VERSION 5.7 ;
  NOWIREEXTENSIONATPIN ON ;
  DIVIDERCHAR "/" ;
  BUSBITCHARS "[]" ;
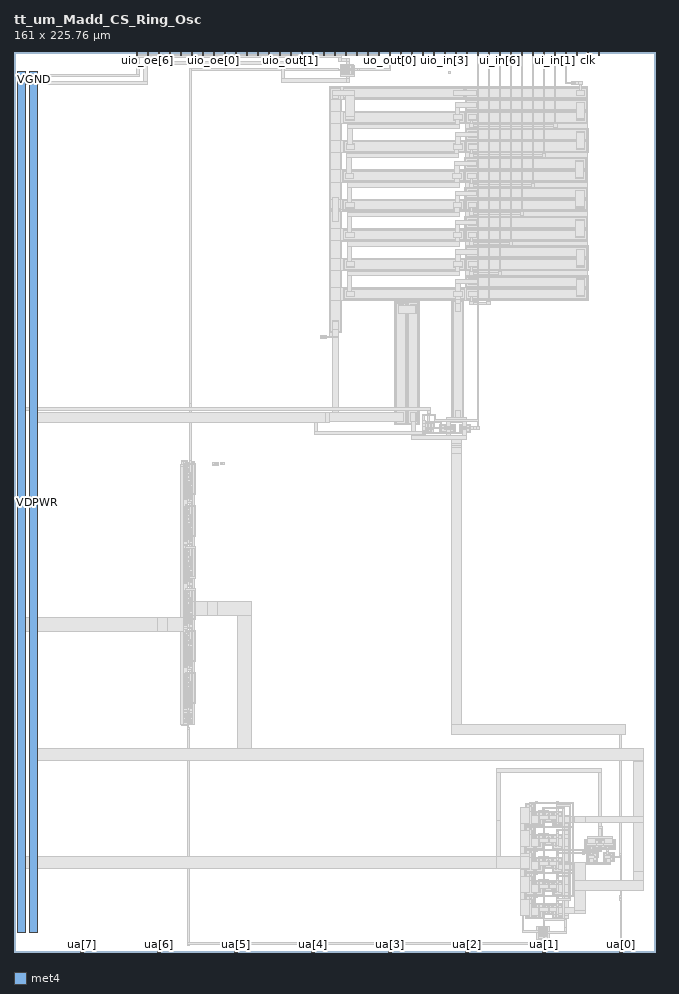
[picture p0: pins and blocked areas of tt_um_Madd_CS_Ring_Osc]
MACRO tt_um_Madd_CS_Ring_Osc
  CLASS BLOCK ;
  FOREIGN tt_um_Madd_CS_Ring_Osc ;
  ORIGIN 0.000 0.000 ;
  SIZE 161.000 BY 225.760 ;
  PIN clk
    DIRECTION INPUT ;
    USE SIGNAL ;
    PORT
      LAYER met4 ;
        RECT 143.830 224.760 144.130 225.760 ;
    END
  END clk
  PIN ena
    DIRECTION INPUT ;
    USE SIGNAL ;
    PORT
      LAYER met4 ;
        RECT 146.590 224.760 146.890 225.760 ;
    END
  END ena
  PIN rst_n
    DIRECTION INPUT ;
    USE SIGNAL ;
    PORT
      LAYER met4 ;
        RECT 141.070 224.760 141.370 225.760 ;
    END
  END rst_n
  PIN ua[0]
    DIRECTION INOUT ;
    USE SIGNAL ;
    ANTENNAGATEAREA 0.500000 ;
    ANTENNADIFFAREA 0.870000 ;
    PORT
      LAYER met4 ;
        RECT 151.810 0.000 152.710 1.000 ;
    END
  END ua[0]
  PIN ua[1]
    DIRECTION INOUT ;
    USE SIGNAL ;
    ANTENNAGATEAREA 0.247500 ;
    ANTENNADIFFAREA 0.891000 ;
    PORT
      LAYER met4 ;
        RECT 132.490 0.000 133.390 1.000 ;
    END
  END ua[1]
  PIN ua[2]
    DIRECTION INOUT ;
    USE SIGNAL ;
    PORT
      LAYER met4 ;
        RECT 113.170 0.000 114.070 1.000 ;
    END
  END ua[2]
  PIN ua[3]
    DIRECTION INOUT ;
    USE SIGNAL ;
    PORT
      LAYER met4 ;
        RECT 93.850 0.000 94.750 1.000 ;
    END
  END ua[3]
  PIN ua[4]
    DIRECTION INOUT ;
    USE SIGNAL ;
    PORT
      LAYER met4 ;
        RECT 74.530 0.000 75.430 1.000 ;
    END
  END ua[4]
  PIN ua[5]
    DIRECTION INOUT ;
    USE SIGNAL ;
    PORT
      LAYER met4 ;
        RECT 55.210 0.000 56.110 1.000 ;
    END
  END ua[5]
  PIN ua[6]
    DIRECTION INOUT ;
    USE SIGNAL ;
    PORT
      LAYER met4 ;
        RECT 35.890 0.000 36.790 1.000 ;
    END
  END ua[6]
  PIN ua[7]
    DIRECTION INOUT ;
    USE SIGNAL ;
    PORT
      LAYER met4 ;
        RECT 16.570 0.000 17.470 1.000 ;
    END
  END ua[7]
  PIN ui_in[0]
    DIRECTION INPUT ;
    USE SIGNAL ;
    PORT
      LAYER met4 ;
        RECT 138.310 224.760 138.610 225.760 ;
    END
  END ui_in[0]
  PIN ui_in[1]
    DIRECTION INPUT ;
    USE SIGNAL ;
    PORT
      LAYER met4 ;
        RECT 135.550 224.760 135.850 225.760 ;
    END
  END ui_in[1]
  PIN ui_in[2]
    DIRECTION INPUT ;
    USE SIGNAL ;
    PORT
      LAYER met4 ;
        RECT 132.790 224.760 133.090 225.760 ;
    END
  END ui_in[2]
  PIN ui_in[3]
    DIRECTION INPUT ;
    USE SIGNAL ;
    PORT
      LAYER met4 ;
        RECT 130.030 224.760 130.330 225.760 ;
    END
  END ui_in[3]
  PIN ui_in[4]
    DIRECTION INPUT ;
    USE SIGNAL ;
    PORT
      LAYER met4 ;
        RECT 127.270 224.760 127.570 225.760 ;
    END
  END ui_in[4]
  PIN ui_in[5]
    DIRECTION INPUT ;
    USE SIGNAL ;
    PORT
      LAYER met4 ;
        RECT 124.510 224.760 124.810 225.760 ;
    END
  END ui_in[5]
  PIN ui_in[6]
    DIRECTION INPUT ;
    USE SIGNAL ;
    PORT
      LAYER met4 ;
        RECT 121.750 224.760 122.050 225.760 ;
    END
  END ui_in[6]
  PIN ui_in[7]
    DIRECTION INPUT ;
    USE SIGNAL ;
    PORT
      LAYER met4 ;
        RECT 118.990 224.760 119.290 225.760 ;
    END
  END ui_in[7]
  PIN uio_in[0]
    DIRECTION INPUT ;
    USE SIGNAL ;
    ANTENNAGATEAREA 0.397500 ;
    PORT
      LAYER met4 ;
        RECT 116.230 224.760 116.530 225.760 ;
    END
  END uio_in[0]
  PIN uio_in[1]
    DIRECTION INPUT ;
    USE SIGNAL ;
    PORT
      LAYER met4 ;
        RECT 113.470 224.760 113.770 225.760 ;
    END
  END uio_in[1]
  PIN uio_in[2]
    DIRECTION INPUT ;
    USE SIGNAL ;
    PORT
      LAYER met4 ;
        RECT 110.710 224.760 111.010 225.760 ;
    END
  END uio_in[2]
  PIN uio_in[3]
    DIRECTION INPUT ;
    USE SIGNAL ;
    PORT
      LAYER met4 ;
        RECT 107.950 224.760 108.250 225.760 ;
    END
  END uio_in[3]
  PIN uio_in[4]
    DIRECTION INPUT ;
    USE SIGNAL ;
    PORT
      LAYER met4 ;
        RECT 105.190 224.760 105.490 225.760 ;
    END
  END uio_in[4]
  PIN uio_in[5]
    DIRECTION INPUT ;
    USE SIGNAL ;
    PORT
      LAYER met4 ;
        RECT 102.430 224.760 102.730 225.760 ;
    END
  END uio_in[5]
  PIN uio_in[6]
    DIRECTION INPUT ;
    USE SIGNAL ;
    PORT
      LAYER met4 ;
        RECT 99.670 224.760 99.970 225.760 ;
    END
  END uio_in[6]
  PIN uio_in[7]
    DIRECTION INPUT ;
    USE SIGNAL ;
    PORT
      LAYER met4 ;
        RECT 96.910 224.760 97.210 225.760 ;
    END
  END uio_in[7]
  PIN uio_oe[0]
    DIRECTION OUTPUT ;
    USE SIGNAL ;
    ANTENNADIFFAREA 343.629578 ;
    PORT
      LAYER met4 ;
        RECT 49.990 224.760 50.290 225.760 ;
    END
  END uio_oe[0]
  PIN uio_oe[1]
    DIRECTION OUTPUT ;
    USE SIGNAL ;
    ANTENNADIFFAREA 343.629578 ;
    PORT
      LAYER met4 ;
        RECT 47.230 224.760 47.530 225.760 ;
    END
  END uio_oe[1]
  PIN uio_oe[2]
    DIRECTION OUTPUT ;
    USE SIGNAL ;
    ANTENNADIFFAREA 343.629578 ;
    PORT
      LAYER met4 ;
        RECT 44.470 224.760 44.770 225.760 ;
    END
  END uio_oe[2]
  PIN uio_oe[3]
    DIRECTION OUTPUT ;
    USE SIGNAL ;
    ANTENNADIFFAREA 343.629578 ;
    PORT
      LAYER met4 ;
        RECT 41.710 224.760 42.010 225.760 ;
    END
  END uio_oe[3]
  PIN uio_oe[4]
    DIRECTION OUTPUT ;
    USE SIGNAL ;
    ANTENNADIFFAREA 343.629578 ;
    PORT
      LAYER met4 ;
        RECT 38.950 224.760 39.250 225.760 ;
    END
  END uio_oe[4]
  PIN uio_oe[5]
    DIRECTION OUTPUT ;
    USE SIGNAL ;
    ANTENNADIFFAREA 343.629578 ;
    PORT
      LAYER met4 ;
        RECT 36.190 224.760 36.490 225.760 ;
    END
  END uio_oe[5]
  PIN uio_oe[6]
    DIRECTION OUTPUT ;
    USE SIGNAL ;
    ANTENNADIFFAREA 343.629578 ;
    PORT
      LAYER met4 ;
        RECT 33.430 224.760 33.730 225.760 ;
    END
  END uio_oe[6]
  PIN uio_oe[7]
    DIRECTION OUTPUT ;
    USE SIGNAL ;
    ANTENNADIFFAREA 343.629578 ;
    PORT
      LAYER met4 ;
        RECT 30.670 224.760 30.970 225.760 ;
    END
  END uio_oe[7]
  PIN uio_out[0]
    DIRECTION OUTPUT ;
    USE SIGNAL ;
    ANTENNADIFFAREA 343.629578 ;
    PORT
      LAYER met4 ;
        RECT 72.070 224.760 72.370 225.760 ;
    END
  END uio_out[0]
  PIN uio_out[1]
    DIRECTION OUTPUT ;
    USE SIGNAL ;
    ANTENNADIFFAREA 343.629578 ;
    PORT
      LAYER met4 ;
        RECT 69.310 224.760 69.610 225.760 ;
    END
  END uio_out[1]
  PIN uio_out[2]
    DIRECTION OUTPUT ;
    USE SIGNAL ;
    ANTENNADIFFAREA 343.629578 ;
    PORT
      LAYER met4 ;
        RECT 66.550 224.760 66.850 225.760 ;
    END
  END uio_out[2]
  PIN uio_out[3]
    DIRECTION OUTPUT ;
    USE SIGNAL ;
    ANTENNADIFFAREA 343.629578 ;
    PORT
      LAYER met4 ;
        RECT 63.790 224.760 64.090 225.760 ;
    END
  END uio_out[3]
  PIN uio_out[4]
    DIRECTION OUTPUT ;
    USE SIGNAL ;
    ANTENNADIFFAREA 343.629578 ;
    PORT
      LAYER met4 ;
        RECT 61.030 224.760 61.330 225.760 ;
    END
  END uio_out[4]
  PIN uio_out[5]
    DIRECTION OUTPUT ;
    USE SIGNAL ;
    ANTENNADIFFAREA 343.629578 ;
    PORT
      LAYER met4 ;
        RECT 58.270 224.760 58.570 225.760 ;
    END
  END uio_out[5]
  PIN uio_out[6]
    DIRECTION OUTPUT ;
    USE SIGNAL ;
    ANTENNADIFFAREA 343.629578 ;
    PORT
      LAYER met4 ;
        RECT 55.510 224.760 55.810 225.760 ;
    END
  END uio_out[6]
  PIN uio_out[7]
    DIRECTION OUTPUT ;
    USE SIGNAL ;
    ANTENNADIFFAREA 343.629578 ;
    PORT
      LAYER met4 ;
        RECT 52.750 224.760 53.050 225.760 ;
    END
  END uio_out[7]
  PIN uo_out[0]
    DIRECTION OUTPUT ;
    USE SIGNAL ;
    ANTENNADIFFAREA 0.891000 ;
    PORT
      LAYER met4 ;
        RECT 94.150 224.760 94.450 225.760 ;
    END
  END uo_out[0]
  PIN uo_out[1]
    DIRECTION OUTPUT ;
    USE SIGNAL ;
    ANTENNADIFFAREA 343.629578 ;
    PORT
      LAYER met4 ;
        RECT 91.390 224.760 91.690 225.760 ;
    END
  END uo_out[1]
  PIN uo_out[2]
    DIRECTION OUTPUT ;
    USE SIGNAL ;
    ANTENNADIFFAREA 343.629578 ;
    PORT
      LAYER met4 ;
        RECT 88.630 224.760 88.930 225.760 ;
    END
  END uo_out[2]
  PIN uo_out[3]
    DIRECTION OUTPUT ;
    USE SIGNAL ;
    ANTENNADIFFAREA 343.629578 ;
    PORT
      LAYER met4 ;
        RECT 85.870 224.760 86.170 225.760 ;
    END
  END uo_out[3]
  PIN uo_out[4]
    DIRECTION OUTPUT ;
    USE SIGNAL ;
    ANTENNADIFFAREA 343.629578 ;
    PORT
      LAYER met4 ;
        RECT 83.110 224.760 83.410 225.760 ;
    END
  END uo_out[4]
  PIN uo_out[5]
    DIRECTION OUTPUT ;
    USE SIGNAL ;
    ANTENNADIFFAREA 343.629578 ;
    PORT
      LAYER met4 ;
        RECT 80.350 224.760 80.650 225.760 ;
    END
  END uo_out[5]
  PIN uo_out[6]
    DIRECTION OUTPUT ;
    USE SIGNAL ;
    ANTENNADIFFAREA 343.629578 ;
    PORT
      LAYER met4 ;
        RECT 77.590 224.760 77.890 225.760 ;
    END
  END uo_out[6]
  PIN uo_out[7]
    DIRECTION OUTPUT ;
    USE SIGNAL ;
    ANTENNADIFFAREA 343.629578 ;
    PORT
      LAYER met4 ;
        RECT 74.830 224.760 75.130 225.760 ;
    END
  END uo_out[7]
  PIN VDPWR
    DIRECTION INOUT ;
    USE POWER ;
    PORT
      LAYER met4 ;
        RECT 1.000 5.000 3.000 220.760 ;
    END
  END VDPWR
  PIN VGND
    DIRECTION INOUT ;
    USE GROUND ;
    PORT
      LAYER met4 ;
        RECT 3.980 4.940 6.000 220.760 ;
    END
  END VGND
  OBS
      LAYER pwell ;
        RECT 82.160 222.395 82.330 222.585 ;
        RECT 85.170 222.400 85.290 222.420 ;
        RECT 84.280 222.395 85.290 222.400 ;
        RECT 82.015 221.700 85.290 222.395 ;
        RECT 82.015 221.485 85.220 221.700 ;
        RECT 84.290 221.480 85.220 221.485 ;
      LAYER nwell ;
        RECT 81.820 219.590 85.420 221.195 ;
      LAYER pwell ;
        RECT 109.000 220.350 109.500 220.850 ;
        RECT 140.750 217.500 142.520 217.650 ;
        RECT 113.160 217.000 143.980 217.040 ;
        RECT 79.110 216.990 82.180 217.000 ;
        RECT 82.380 216.990 143.980 217.000 ;
        RECT 79.110 213.970 143.980 216.990 ;
        RECT 79.110 213.930 143.970 213.970 ;
        RECT 79.110 213.920 82.730 213.930 ;
        RECT 79.110 210.920 82.180 213.920 ;
        RECT 113.150 210.920 143.970 213.930 ;
        RECT 79.110 207.850 143.970 210.920 ;
        RECT 79.110 203.540 82.180 207.850 ;
        RECT 113.210 206.600 143.970 207.850 ;
        RECT 113.210 203.540 144.060 206.600 ;
        RECT 79.110 200.470 144.060 203.540 ;
        RECT 79.110 196.220 82.180 200.470 ;
        RECT 113.210 199.270 143.970 200.470 ;
        RECT 79.110 196.210 82.630 196.220 ;
        RECT 112.970 196.210 143.970 199.270 ;
        RECT 79.110 193.150 143.970 196.210 ;
        RECT 79.110 188.800 82.180 193.150 ;
        RECT 82.240 193.140 143.970 193.150 ;
        RECT 113.210 191.890 143.970 193.140 ;
        RECT 113.060 188.830 143.970 191.890 ;
        RECT 82.330 188.800 143.970 188.830 ;
        RECT 79.110 186.180 143.970 188.800 ;
        RECT 81.660 186.170 143.970 186.180 ;
        RECT 79.110 185.760 143.970 186.170 ;
        RECT 79.110 185.730 82.750 185.760 ;
        RECT 79.110 181.450 82.180 185.730 ;
        RECT 113.210 184.480 143.970 185.760 ;
        RECT 79.110 181.420 82.750 181.450 ;
        RECT 113.100 181.420 143.970 184.480 ;
        RECT 79.110 178.380 143.970 181.420 ;
        RECT 79.110 174.030 82.180 178.380 ;
        RECT 82.370 178.350 143.970 178.380 ;
        RECT 113.210 177.100 143.970 178.350 ;
        RECT 113.190 174.040 144.010 177.100 ;
        RECT 82.460 174.030 144.010 174.040 ;
        RECT 79.110 170.970 144.010 174.030 ;
        RECT 79.110 170.960 82.960 170.970 ;
        RECT 79.110 166.600 82.180 170.960 ;
        RECT 113.210 169.670 143.970 170.970 ;
        RECT 113.210 166.610 144.030 169.670 ;
        RECT 82.480 166.600 144.030 166.610 ;
        RECT 79.110 163.540 144.030 166.600 ;
        RECT 79.110 163.530 82.760 163.540 ;
        RECT 79.110 155.350 82.180 163.530 ;
        RECT 95.530 163.120 101.670 163.540 ;
      LAYER nwell ;
        RECT 76.830 153.840 78.435 154.680 ;
      LAYER pwell ;
        RECT 79.110 154.475 79.970 155.350 ;
        RECT 78.765 154.045 79.970 154.475 ;
        RECT 79.110 154.030 79.970 154.045 ;
        RECT 95.550 132.330 101.670 163.120 ;
        RECT 95.550 132.310 98.620 132.330 ;
      LAYER nwell ;
        RECT 103.180 131.495 105.400 133.100 ;
      LAYER pwell ;
        RECT 109.800 132.760 112.870 163.540 ;
        RECT 114.230 163.050 116.110 163.200 ;
        RECT 103.580 130.295 104.510 131.205 ;
        RECT 104.765 130.380 105.195 131.165 ;
      LAYER nwell ;
        RECT 106.830 130.330 110.670 132.440 ;
      LAYER pwell ;
        RECT 111.835 130.330 114.625 132.440 ;
        RECT 103.580 130.275 103.685 130.295 ;
        RECT 103.515 130.105 103.685 130.275 ;
      LAYER nwell ;
        RECT 42.000 122.360 43.605 123.200 ;
      LAYER pwell ;
        RECT 43.935 122.820 44.720 122.995 ;
        RECT 43.890 122.750 44.810 122.820 ;
      LAYER nwell ;
        RECT 41.990 113.430 43.595 122.360 ;
      LAYER pwell ;
        RECT 43.880 121.940 44.820 122.750 ;
      LAYER nwell ;
        RECT 49.740 122.060 51.345 122.900 ;
      LAYER pwell ;
        RECT 51.675 122.265 52.460 122.695 ;
        RECT 43.885 119.400 44.795 121.940 ;
        RECT 44.115 117.860 44.795 119.400 ;
        RECT 43.895 116.950 44.795 117.860 ;
        RECT 44.115 113.745 44.795 116.950 ;
        RECT 44.115 113.575 44.985 113.745 ;
        RECT 44.115 113.500 44.795 113.575 ;
      LAYER nwell ;
        RECT 41.990 111.780 43.600 113.430 ;
        RECT 41.990 102.900 43.595 111.780 ;
      LAYER pwell ;
        RECT 44.100 111.655 44.800 113.500 ;
        RECT 43.885 111.300 44.800 111.655 ;
        RECT 43.885 108.890 44.795 111.300 ;
        RECT 44.115 107.350 44.795 108.890 ;
        RECT 43.895 106.440 44.795 107.350 ;
        RECT 44.115 103.235 44.795 106.440 ;
        RECT 44.115 103.200 44.985 103.235 ;
        RECT 44.100 103.065 44.985 103.200 ;
      LAYER nwell ;
        RECT 41.990 101.250 43.600 102.900 ;
      LAYER pwell ;
        RECT 44.100 102.265 44.800 103.065 ;
        RECT 43.925 101.835 44.800 102.265 ;
      LAYER nwell ;
        RECT 41.990 92.430 43.595 101.250 ;
      LAYER pwell ;
        RECT 44.100 101.165 44.800 101.835 ;
        RECT 43.885 101.000 44.800 101.165 ;
        RECT 43.885 98.400 44.795 101.000 ;
        RECT 44.115 96.860 44.795 98.400 ;
        RECT 43.895 95.950 44.795 96.860 ;
        RECT 44.115 92.745 44.795 95.950 ;
        RECT 44.115 92.600 44.985 92.745 ;
        RECT 44.100 92.575 44.985 92.600 ;
      LAYER nwell ;
        RECT 41.990 90.780 43.600 92.430 ;
        RECT 41.990 81.900 43.595 90.780 ;
      LAYER pwell ;
        RECT 44.100 90.655 44.800 92.575 ;
        RECT 43.885 90.400 44.800 90.655 ;
        RECT 43.885 87.890 44.795 90.400 ;
        RECT 44.115 86.350 44.795 87.890 ;
        RECT 43.895 85.440 44.795 86.350 ;
        RECT 44.115 82.235 44.795 85.440 ;
        RECT 44.115 82.100 44.985 82.235 ;
        RECT 44.100 82.065 44.985 82.100 ;
      LAYER nwell ;
        RECT 41.990 80.250 43.600 81.900 ;
      LAYER pwell ;
        RECT 44.100 81.375 44.800 82.065 ;
        RECT 43.925 80.945 44.800 81.375 ;
      LAYER nwell ;
        RECT 41.990 71.400 43.595 80.250 ;
      LAYER pwell ;
        RECT 44.100 80.165 44.800 80.945 ;
        RECT 43.885 79.900 44.800 80.165 ;
        RECT 43.885 77.400 44.795 79.900 ;
        RECT 44.115 75.860 44.795 77.400 ;
        RECT 43.895 74.950 44.795 75.860 ;
        RECT 44.115 71.745 44.795 74.950 ;
        RECT 44.115 71.700 44.985 71.745 ;
        RECT 44.100 71.575 44.985 71.700 ;
      LAYER nwell ;
        RECT 41.990 69.750 43.600 71.400 ;
        RECT 41.990 61.300 43.595 69.750 ;
      LAYER pwell ;
        RECT 44.100 69.655 44.800 71.575 ;
        RECT 43.885 69.500 44.800 69.655 ;
        RECT 43.885 66.890 44.795 69.500 ;
        RECT 44.115 65.350 44.795 66.890 ;
        RECT 43.895 64.440 44.795 65.350 ;
      LAYER nwell ;
        RECT 41.990 60.460 43.600 61.300 ;
      LAYER pwell ;
        RECT 44.115 61.235 44.795 64.440 ;
        RECT 44.115 61.065 44.985 61.235 ;
        RECT 44.115 61.010 44.795 61.065 ;
      LAYER nwell ;
        RECT 41.990 56.880 43.595 60.460 ;
      LAYER pwell ;
        RECT 44.100 60.280 44.820 61.010 ;
        RECT 43.880 60.230 44.820 60.280 ;
        RECT 43.880 59.350 44.800 60.230 ;
        RECT 43.885 59.340 44.800 59.350 ;
        RECT 43.885 57.390 44.795 59.340 ;
        RECT 43.885 57.220 44.985 57.390 ;
        RECT 43.885 57.075 44.795 57.220 ;
      LAYER nwell ;
        RECT 128.310 35.350 130.770 37.350 ;
        RECT 128.310 31.545 132.820 35.350 ;
      LAYER pwell ;
        RECT 133.055 32.510 137.570 35.300 ;
      LAYER nwell ;
        RECT 128.305 31.510 132.820 31.545 ;
      LAYER pwell ;
        RECT 135.110 31.510 137.570 32.510 ;
      LAYER nwell ;
        RECT 128.305 29.545 130.765 31.510 ;
        RECT 128.305 25.705 132.815 29.545 ;
      LAYER pwell ;
        RECT 133.050 26.705 137.565 29.495 ;
        RECT 135.105 25.705 137.565 26.705 ;
      LAYER nwell ;
        RECT 143.185 25.815 150.805 28.275 ;
        RECT 128.305 23.750 130.765 25.705 ;
        RECT 128.305 19.910 132.815 23.750 ;
      LAYER pwell ;
        RECT 133.050 20.910 137.565 23.700 ;
        RECT 143.635 22.610 146.425 25.070 ;
        RECT 147.770 22.605 150.560 25.065 ;
        RECT 135.105 19.910 137.565 20.910 ;
      LAYER nwell ;
        RECT 128.310 17.950 130.770 19.910 ;
        RECT 128.310 14.150 132.820 17.950 ;
      LAYER pwell ;
        RECT 133.055 15.110 137.570 17.900 ;
      LAYER nwell ;
        RECT 128.305 14.110 132.820 14.150 ;
      LAYER pwell ;
        RECT 135.110 14.110 137.570 15.110 ;
      LAYER nwell ;
        RECT 128.305 12.150 130.765 14.110 ;
        RECT 128.305 8.310 132.815 12.150 ;
      LAYER pwell ;
        RECT 133.050 9.310 137.565 12.100 ;
        RECT 135.105 8.310 137.565 9.310 ;
      LAYER nwell ;
        RECT 131.220 2.920 132.825 6.520 ;
      LAYER pwell ;
        RECT 133.115 6.180 134.025 6.325 ;
        RECT 133.115 6.010 134.215 6.180 ;
        RECT 133.115 4.060 134.025 6.010 ;
        RECT 133.115 4.050 134.030 4.060 ;
        RECT 133.110 3.130 134.030 4.050 ;
        RECT 133.110 3.120 133.990 3.130 ;
      LAYER li1 ;
        RECT 82.010 222.415 85.230 222.585 ;
        RECT 82.185 221.765 82.355 222.245 ;
        RECT 82.535 221.935 82.775 222.415 ;
        RECT 83.025 221.765 83.195 222.245 ;
        RECT 83.365 221.935 83.695 222.415 ;
        RECT 83.865 221.765 84.035 222.245 ;
        RECT 82.185 221.595 82.820 221.765 ;
        RECT 83.025 221.595 84.035 221.765 ;
        RECT 84.205 221.615 84.535 222.415 ;
        RECT 84.855 221.690 85.145 222.415 ;
        RECT 82.650 221.425 82.820 221.595 ;
        RECT 82.100 221.185 82.480 221.425 ;
        RECT 82.650 221.255 83.150 221.425 ;
        RECT 82.650 221.015 82.820 221.255 ;
        RECT 83.540 221.055 84.035 221.595 ;
        RECT 82.105 220.845 82.820 221.015 ;
        RECT 83.025 220.885 84.035 221.055 ;
        RECT 82.105 220.035 82.435 220.845 ;
        RECT 82.605 219.865 82.845 220.665 ;
        RECT 83.025 220.035 83.195 220.885 ;
        RECT 83.365 219.865 83.695 220.665 ;
        RECT 83.865 220.035 84.035 220.885 ;
        RECT 84.205 219.865 84.535 221.015 ;
        RECT 84.855 219.865 85.145 221.030 ;
        RECT 109.000 220.350 109.500 220.850 ;
        RECT 82.010 219.695 85.230 219.865 ;
        RECT 79.290 216.650 82.000 216.820 ;
        RECT 79.290 186.530 79.460 216.650 ;
        RECT 79.940 214.010 81.350 216.170 ;
        RECT 79.940 187.010 81.350 189.170 ;
        RECT 81.830 186.530 82.000 216.650 ;
        RECT 82.560 216.650 113.020 216.820 ;
        RECT 82.560 214.280 82.730 216.650 ;
        RECT 83.210 214.760 85.370 216.170 ;
        RECT 110.210 214.760 112.370 216.170 ;
        RECT 112.850 214.280 113.020 216.650 ;
        RECT 82.560 214.110 113.020 214.280 ;
        RECT 113.340 216.690 143.800 216.860 ;
        RECT 113.340 214.320 113.510 216.690 ;
        RECT 113.990 214.800 116.150 216.210 ;
        RECT 140.990 214.800 143.150 216.210 ;
        RECT 143.630 214.320 143.800 216.690 ;
        RECT 113.340 214.150 143.800 214.320 ;
        RECT 113.330 213.630 143.790 213.800 ;
        RECT 113.330 211.260 113.500 213.630 ;
        RECT 113.980 211.740 116.140 213.150 ;
        RECT 140.980 211.740 143.140 213.150 ;
        RECT 143.620 211.260 143.790 213.630 ;
        RECT 113.330 211.090 143.790 211.260 ;
        RECT 82.600 210.570 113.060 210.740 ;
        RECT 82.600 208.200 82.770 210.570 ;
        RECT 83.250 208.680 85.410 210.090 ;
        RECT 110.250 208.680 112.410 210.090 ;
        RECT 112.890 208.200 113.060 210.570 ;
        RECT 82.600 208.030 113.060 208.200 ;
        RECT 113.330 210.570 143.790 210.740 ;
        RECT 113.330 208.200 113.500 210.570 ;
        RECT 113.980 208.680 116.140 210.090 ;
        RECT 140.980 208.680 143.140 210.090 ;
        RECT 143.620 208.200 143.790 210.570 ;
        RECT 113.330 208.030 143.790 208.200 ;
        RECT 113.420 206.250 143.880 206.420 ;
        RECT 113.420 203.880 113.590 206.250 ;
        RECT 114.070 204.360 116.230 205.770 ;
        RECT 141.070 204.360 143.230 205.770 ;
        RECT 143.710 203.880 143.880 206.250 ;
        RECT 113.420 203.710 143.880 203.880 ;
        RECT 82.690 203.190 113.150 203.360 ;
        RECT 82.690 200.820 82.860 203.190 ;
        RECT 83.340 201.300 85.500 202.710 ;
        RECT 110.340 201.300 112.500 202.710 ;
        RECT 112.980 200.820 113.150 203.190 ;
        RECT 82.690 200.650 113.150 200.820 ;
        RECT 113.420 203.190 143.880 203.360 ;
        RECT 113.420 200.820 113.590 203.190 ;
        RECT 114.070 201.300 116.230 202.710 ;
        RECT 141.070 201.300 143.230 202.710 ;
        RECT 143.710 200.820 143.880 203.190 ;
        RECT 113.420 200.650 143.880 200.820 ;
        RECT 113.150 198.920 143.610 199.090 ;
        RECT 113.150 196.550 113.320 198.920 ;
        RECT 113.800 197.030 115.960 198.440 ;
        RECT 140.800 197.030 142.960 198.440 ;
        RECT 143.440 196.550 143.610 198.920 ;
        RECT 113.150 196.380 143.610 196.550 ;
        RECT 82.420 195.860 112.880 196.030 ;
        RECT 82.420 193.490 82.590 195.860 ;
        RECT 83.070 193.970 85.230 195.380 ;
        RECT 110.070 193.970 112.230 195.380 ;
        RECT 112.710 193.490 112.880 195.860 ;
        RECT 82.420 193.320 112.880 193.490 ;
        RECT 113.150 195.860 143.610 196.030 ;
        RECT 113.150 193.490 113.320 195.860 ;
        RECT 113.800 193.970 115.960 195.380 ;
        RECT 140.800 193.970 142.960 195.380 ;
        RECT 143.440 193.490 143.610 195.860 ;
        RECT 113.150 193.320 143.610 193.490 ;
        RECT 113.240 191.540 143.700 191.710 ;
        RECT 113.240 189.170 113.410 191.540 ;
        RECT 113.890 189.650 116.050 191.060 ;
        RECT 140.890 189.650 143.050 191.060 ;
        RECT 143.530 189.170 143.700 191.540 ;
        RECT 113.240 189.000 143.700 189.170 ;
        RECT 79.290 186.360 82.000 186.530 ;
        RECT 82.510 188.480 112.970 188.650 ;
        RECT 82.510 186.110 82.680 188.480 ;
        RECT 83.160 186.590 85.320 188.000 ;
        RECT 110.160 186.590 112.320 188.000 ;
        RECT 112.800 186.110 112.970 188.480 ;
        RECT 79.290 185.820 82.000 185.990 ;
        RECT 82.510 185.940 112.970 186.110 ;
        RECT 113.240 188.480 143.700 188.650 ;
        RECT 113.240 186.110 113.410 188.480 ;
        RECT 113.890 186.590 116.050 188.000 ;
        RECT 140.890 186.590 143.050 188.000 ;
        RECT 143.530 186.110 143.700 188.480 ;
        RECT 113.240 185.940 143.700 186.110 ;
        RECT 79.290 155.700 79.460 185.820 ;
        RECT 79.940 183.180 81.350 185.340 ;
        RECT 79.940 156.180 81.350 158.340 ;
        RECT 81.830 155.700 82.000 185.820 ;
        RECT 113.280 184.130 143.740 184.300 ;
        RECT 113.280 181.760 113.450 184.130 ;
        RECT 113.930 182.240 116.090 183.650 ;
        RECT 140.930 182.240 143.090 183.650 ;
        RECT 143.570 181.760 143.740 184.130 ;
        RECT 113.280 181.590 143.740 181.760 ;
        RECT 82.550 181.070 113.010 181.240 ;
        RECT 82.550 178.700 82.720 181.070 ;
        RECT 83.200 179.180 85.360 180.590 ;
        RECT 110.200 179.180 112.360 180.590 ;
        RECT 112.840 178.700 113.010 181.070 ;
        RECT 82.550 178.530 113.010 178.700 ;
        RECT 113.280 181.070 143.740 181.240 ;
        RECT 113.280 178.700 113.450 181.070 ;
        RECT 113.930 179.180 116.090 180.590 ;
        RECT 140.930 179.180 143.090 180.590 ;
        RECT 143.570 178.700 143.740 181.070 ;
        RECT 113.280 178.530 143.740 178.700 ;
        RECT 113.370 176.750 143.830 176.920 ;
        RECT 113.370 174.380 113.540 176.750 ;
        RECT 114.020 174.860 116.180 176.270 ;
        RECT 141.020 174.860 143.180 176.270 ;
        RECT 143.660 174.380 143.830 176.750 ;
        RECT 113.370 174.210 143.830 174.380 ;
        RECT 82.640 173.690 113.100 173.860 ;
        RECT 82.640 171.320 82.810 173.690 ;
        RECT 83.290 171.800 85.450 173.210 ;
        RECT 110.290 171.800 112.450 173.210 ;
        RECT 112.930 171.320 113.100 173.690 ;
        RECT 82.640 171.150 113.100 171.320 ;
        RECT 113.370 173.690 143.830 173.860 ;
        RECT 113.370 171.320 113.540 173.690 ;
        RECT 114.020 171.800 116.180 173.210 ;
        RECT 141.020 171.800 143.180 173.210 ;
        RECT 143.660 171.320 143.830 173.690 ;
        RECT 113.370 171.150 143.830 171.320 ;
        RECT 113.390 169.320 143.850 169.490 ;
        RECT 113.390 166.950 113.560 169.320 ;
        RECT 114.040 167.430 116.200 168.840 ;
        RECT 141.040 167.430 143.200 168.840 ;
        RECT 143.680 166.950 143.850 169.320 ;
        RECT 113.390 166.780 143.850 166.950 ;
        RECT 82.660 166.260 113.120 166.430 ;
        RECT 82.660 163.890 82.830 166.260 ;
        RECT 83.310 164.370 85.470 165.780 ;
        RECT 110.310 164.370 112.470 165.780 ;
        RECT 112.950 163.890 113.120 166.260 ;
        RECT 82.660 163.720 113.120 163.890 ;
        RECT 113.390 166.260 143.850 166.430 ;
        RECT 113.390 163.890 113.560 166.260 ;
        RECT 114.040 164.370 116.200 165.780 ;
        RECT 141.040 164.370 143.200 165.780 ;
        RECT 143.680 163.890 143.850 166.260 ;
        RECT 113.390 163.720 143.850 163.890 ;
        RECT 109.980 163.230 112.690 163.400 ;
        RECT 79.290 155.530 82.000 155.700 ;
        RECT 95.730 162.780 98.440 162.950 ;
        RECT 76.935 154.405 77.105 154.490 ;
        RECT 79.655 154.405 79.825 154.490 ;
        RECT 76.935 154.115 78.270 154.405 ;
        RECT 78.930 154.115 79.825 154.405 ;
        RECT 76.935 154.030 77.105 154.115 ;
        RECT 79.655 154.030 79.825 154.115 ;
        RECT 95.730 132.660 95.900 162.780 ;
        RECT 96.380 160.140 97.790 162.300 ;
        RECT 96.380 133.140 97.790 135.300 ;
        RECT 98.270 132.660 98.440 162.780 ;
        RECT 95.730 132.490 98.440 132.660 ;
        RECT 98.780 162.800 101.490 162.970 ;
        RECT 98.780 132.680 98.950 162.800 ;
        RECT 99.430 160.160 100.840 162.320 ;
        RECT 99.430 133.160 100.840 135.320 ;
        RECT 101.320 132.680 101.490 162.800 ;
        RECT 109.980 133.110 110.150 163.230 ;
        RECT 110.630 160.590 112.040 162.750 ;
        RECT 110.630 133.590 112.040 135.750 ;
        RECT 112.520 133.110 112.690 163.230 ;
        RECT 103.370 132.825 105.210 132.995 ;
        RECT 109.980 132.940 112.690 133.110 ;
        RECT 98.780 132.510 101.490 132.680 ;
        RECT 103.710 131.685 103.920 132.825 ;
        RECT 104.090 131.675 104.420 132.655 ;
        RECT 103.690 131.265 104.020 131.505 ;
        RECT 103.690 130.275 103.920 131.095 ;
        RECT 104.190 131.075 104.420 131.675 ;
        RECT 104.835 131.660 105.125 132.825 ;
        RECT 107.010 132.090 110.490 132.260 ;
        RECT 104.090 130.445 104.420 131.075 ;
        RECT 104.835 130.275 105.125 131.000 ;
        RECT 107.010 130.680 107.180 132.090 ;
        RECT 107.525 131.220 107.695 131.550 ;
        RECT 107.910 131.520 109.950 131.690 ;
        RECT 107.910 131.080 109.950 131.250 ;
        RECT 110.320 130.680 110.490 132.090 ;
        RECT 112.015 132.090 114.445 132.260 ;
        RECT 112.015 130.680 112.185 132.090 ;
        RECT 112.555 131.520 113.595 131.690 ;
        RECT 112.555 131.080 113.595 131.250 ;
        RECT 113.765 131.220 113.935 131.550 ;
        RECT 114.275 130.680 114.445 132.090 ;
        RECT 107.010 130.510 110.490 130.680 ;
        RECT 112.010 130.510 114.445 130.680 ;
        RECT 103.370 130.105 105.210 130.275 ;
        RECT 42.105 122.925 42.275 123.010 ;
        RECT 44.825 122.925 44.995 123.010 ;
        RECT 42.105 122.635 43.440 122.925 ;
        RECT 44.100 122.635 44.995 122.925 ;
        RECT 42.105 122.550 42.275 122.635 ;
        RECT 44.825 122.550 44.995 122.635 ;
        RECT 49.845 122.625 50.015 122.710 ;
        RECT 52.565 122.625 52.735 122.710 ;
        RECT 49.845 122.335 51.180 122.625 ;
        RECT 51.840 122.335 52.735 122.625 ;
        RECT 49.845 122.250 50.015 122.335 ;
        RECT 52.565 122.250 52.735 122.335 ;
        RECT 42.095 121.575 42.265 122.170 ;
        RECT 42.435 121.845 44.645 122.080 ;
        RECT 42.435 121.745 43.420 121.845 ;
        RECT 43.990 121.825 44.645 121.845 ;
        RECT 42.095 121.360 43.405 121.575 ;
        RECT 42.095 120.150 42.265 121.360 ;
        RECT 43.575 121.170 43.905 121.675 ;
        RECT 44.815 121.655 44.985 122.170 ;
        RECT 44.355 121.335 44.985 121.655 ;
        RECT 42.455 121.100 43.905 121.170 ;
        RECT 42.455 120.900 44.555 121.100 ;
        RECT 42.455 120.840 43.185 120.900 ;
        RECT 44.285 120.850 44.555 120.900 ;
        RECT 43.325 120.660 44.160 120.730 ;
        RECT 43.325 120.650 44.595 120.660 ;
        RECT 42.480 120.540 44.595 120.650 ;
        RECT 42.480 120.495 43.455 120.540 ;
        RECT 42.480 120.320 43.405 120.495 ;
        RECT 44.035 120.485 44.595 120.540 ;
        RECT 42.095 119.980 43.275 120.150 ;
        RECT 42.095 119.235 42.265 119.980 ;
        RECT 43.575 119.820 43.905 120.370 ;
        RECT 44.075 120.330 44.595 120.485 ;
        RECT 44.815 120.160 44.985 121.335 ;
        RECT 44.205 119.990 44.985 120.160 ;
        RECT 43.575 119.810 44.600 119.820 ;
        RECT 42.435 119.620 44.600 119.810 ;
        RECT 42.435 119.470 43.370 119.620 ;
        RECT 44.075 119.490 44.600 119.620 ;
        RECT 42.095 118.920 42.765 119.235 ;
        RECT 42.095 117.210 42.265 118.920 ;
        RECT 42.995 118.910 43.370 119.470 ;
        RECT 43.575 118.740 43.905 119.450 ;
        RECT 44.815 119.225 44.985 119.990 ;
        RECT 44.285 119.015 44.985 119.225 ;
        RECT 42.565 118.570 44.535 118.740 ;
        RECT 42.565 117.855 42.735 118.570 ;
        RECT 42.905 118.080 44.195 118.400 ;
        RECT 43.865 117.935 44.195 118.080 ;
        RECT 44.365 117.955 44.535 118.570 ;
        RECT 42.935 117.720 43.655 117.910 ;
        RECT 42.435 117.550 42.765 117.630 ;
        RECT 44.365 117.550 44.535 117.785 ;
        RECT 42.435 117.380 44.535 117.550 ;
        RECT 42.095 117.040 43.065 117.210 ;
        RECT 43.325 117.040 43.655 117.210 ;
        RECT 42.095 115.135 42.265 117.040 ;
        RECT 43.325 116.870 43.585 117.040 ;
        RECT 43.835 116.920 44.135 117.380 ;
        RECT 44.815 117.200 44.985 119.015 ;
        RECT 42.540 116.700 43.585 116.870 ;
        RECT 43.805 116.720 44.135 116.920 ;
        RECT 44.315 116.830 44.985 117.200 ;
        RECT 42.540 115.765 42.710 116.700 ;
        RECT 42.880 116.170 43.245 116.530 ;
        RECT 43.415 116.510 43.585 116.700 ;
        RECT 43.415 116.340 44.535 116.510 ;
        RECT 42.880 116.000 44.165 116.170 ;
        RECT 43.180 115.590 43.775 115.830 ;
        RECT 43.945 115.645 44.165 116.000 ;
        RECT 44.365 115.835 44.535 116.340 ;
        RECT 42.435 115.420 42.990 115.555 ;
        RECT 44.365 115.475 44.535 115.640 ;
        RECT 44.095 115.420 44.535 115.475 ;
        RECT 42.435 115.305 44.535 115.420 ;
        RECT 42.860 115.250 44.225 115.305 ;
        RECT 44.815 115.135 44.985 116.830 ;
        RECT 42.095 114.870 42.725 115.135 ;
        RECT 42.095 114.275 42.265 114.870 ;
        RECT 43.235 114.800 44.185 115.080 ;
        RECT 44.355 114.885 44.985 115.135 ;
        RECT 42.435 114.445 44.555 114.630 ;
        RECT 44.815 114.275 44.985 114.885 ;
        RECT 42.095 113.945 42.765 114.275 ;
        RECT 42.935 114.040 44.265 114.270 ;
        RECT 42.095 113.430 42.265 113.945 ;
        RECT 42.935 113.775 43.105 114.040 ;
        RECT 42.435 113.605 43.105 113.775 ;
        RECT 43.275 113.520 43.925 113.870 ;
        RECT 44.095 113.775 44.265 114.040 ;
        RECT 44.435 113.945 44.985 114.275 ;
        RECT 44.095 113.605 44.555 113.775 ;
        RECT 44.815 113.430 44.985 113.945 ;
        RECT 42.095 111.065 42.265 111.660 ;
        RECT 42.435 111.335 44.645 111.570 ;
        RECT 42.435 111.235 43.420 111.335 ;
        RECT 43.990 111.315 44.645 111.335 ;
        RECT 42.095 110.850 43.405 111.065 ;
        RECT 42.095 109.640 42.265 110.850 ;
        RECT 43.575 110.660 43.905 111.165 ;
        RECT 44.815 111.145 44.985 111.660 ;
        RECT 44.355 110.825 44.985 111.145 ;
        RECT 42.455 110.590 43.905 110.660 ;
        RECT 42.455 110.390 44.555 110.590 ;
        RECT 42.455 110.330 43.185 110.390 ;
        RECT 44.285 110.340 44.555 110.390 ;
        RECT 43.325 110.150 44.160 110.220 ;
        RECT 43.325 110.140 44.595 110.150 ;
        RECT 42.480 110.030 44.595 110.140 ;
        RECT 42.480 109.985 43.455 110.030 ;
        RECT 42.480 109.810 43.405 109.985 ;
        RECT 44.035 109.975 44.595 110.030 ;
        RECT 42.095 109.470 43.275 109.640 ;
        RECT 42.095 108.725 42.265 109.470 ;
        RECT 43.575 109.310 43.905 109.860 ;
        RECT 44.075 109.820 44.595 109.975 ;
        RECT 44.815 109.650 44.985 110.825 ;
        RECT 44.205 109.480 44.985 109.650 ;
        RECT 43.575 109.300 44.600 109.310 ;
        RECT 42.435 109.110 44.600 109.300 ;
        RECT 42.435 108.960 43.370 109.110 ;
        RECT 44.075 108.980 44.600 109.110 ;
        RECT 42.095 108.410 42.765 108.725 ;
        RECT 42.095 106.700 42.265 108.410 ;
        RECT 42.995 108.400 43.370 108.960 ;
        RECT 43.575 108.230 43.905 108.940 ;
        RECT 44.815 108.715 44.985 109.480 ;
        RECT 44.285 108.505 44.985 108.715 ;
        RECT 42.565 108.060 44.535 108.230 ;
        RECT 42.565 107.345 42.735 108.060 ;
        RECT 42.905 107.570 44.195 107.890 ;
        RECT 43.865 107.425 44.195 107.570 ;
        RECT 44.365 107.445 44.535 108.060 ;
        RECT 42.935 107.210 43.655 107.400 ;
        RECT 42.435 107.040 42.765 107.120 ;
        RECT 44.365 107.040 44.535 107.275 ;
        RECT 42.435 106.870 44.535 107.040 ;
        RECT 42.095 106.530 43.065 106.700 ;
        RECT 43.325 106.530 43.655 106.700 ;
        RECT 42.095 104.625 42.265 106.530 ;
        RECT 43.325 106.360 43.585 106.530 ;
        RECT 43.835 106.410 44.135 106.870 ;
        RECT 44.815 106.690 44.985 108.505 ;
        RECT 42.540 106.190 43.585 106.360 ;
        RECT 43.805 106.210 44.135 106.410 ;
        RECT 44.315 106.320 44.985 106.690 ;
        RECT 42.540 105.255 42.710 106.190 ;
        RECT 42.880 105.660 43.245 106.020 ;
        RECT 43.415 106.000 43.585 106.190 ;
        RECT 43.415 105.830 44.535 106.000 ;
        RECT 42.880 105.490 44.165 105.660 ;
        RECT 43.180 105.080 43.775 105.320 ;
        RECT 43.945 105.135 44.165 105.490 ;
        RECT 44.365 105.325 44.535 105.830 ;
        RECT 42.435 104.910 42.990 105.045 ;
        RECT 44.365 104.965 44.535 105.130 ;
        RECT 44.095 104.910 44.535 104.965 ;
        RECT 42.435 104.795 44.535 104.910 ;
        RECT 42.860 104.740 44.225 104.795 ;
        RECT 44.815 104.625 44.985 106.320 ;
        RECT 42.095 104.360 42.725 104.625 ;
        RECT 42.095 103.765 42.265 104.360 ;
        RECT 43.235 104.290 44.185 104.570 ;
        RECT 44.355 104.375 44.985 104.625 ;
        RECT 42.435 103.935 44.555 104.120 ;
        RECT 44.815 103.765 44.985 104.375 ;
        RECT 42.095 103.435 42.765 103.765 ;
        RECT 42.935 103.530 44.265 103.760 ;
        RECT 42.095 102.920 42.265 103.435 ;
        RECT 42.935 103.265 43.105 103.530 ;
        RECT 42.435 103.095 43.105 103.265 ;
        RECT 43.275 103.010 43.925 103.360 ;
        RECT 44.095 103.265 44.265 103.530 ;
        RECT 44.435 103.435 44.985 103.765 ;
        RECT 44.095 103.095 44.555 103.265 ;
        RECT 44.815 102.920 44.985 103.435 ;
        RECT 42.095 102.195 42.265 102.280 ;
        RECT 44.815 102.195 44.985 102.280 ;
        RECT 42.095 101.905 43.430 102.195 ;
        RECT 44.090 101.905 44.985 102.195 ;
        RECT 42.095 101.820 42.265 101.905 ;
        RECT 44.815 101.820 44.985 101.905 ;
        RECT 42.095 100.575 42.265 101.170 ;
        RECT 42.435 100.845 44.645 101.080 ;
        RECT 42.435 100.745 43.420 100.845 ;
        RECT 43.990 100.825 44.645 100.845 ;
        RECT 42.095 100.360 43.405 100.575 ;
        RECT 42.095 99.150 42.265 100.360 ;
        RECT 43.575 100.170 43.905 100.675 ;
        RECT 44.815 100.655 44.985 101.170 ;
        RECT 44.355 100.335 44.985 100.655 ;
        RECT 42.455 100.100 43.905 100.170 ;
        RECT 42.455 99.900 44.555 100.100 ;
        RECT 42.455 99.840 43.185 99.900 ;
        RECT 44.285 99.850 44.555 99.900 ;
        RECT 43.325 99.660 44.160 99.730 ;
        RECT 43.325 99.650 44.595 99.660 ;
        RECT 42.480 99.540 44.595 99.650 ;
        RECT 42.480 99.495 43.455 99.540 ;
        RECT 42.480 99.320 43.405 99.495 ;
        RECT 44.035 99.485 44.595 99.540 ;
        RECT 42.095 98.980 43.275 99.150 ;
        RECT 42.095 98.235 42.265 98.980 ;
        RECT 43.575 98.820 43.905 99.370 ;
        RECT 44.075 99.330 44.595 99.485 ;
        RECT 44.815 99.160 44.985 100.335 ;
        RECT 44.205 98.990 44.985 99.160 ;
        RECT 43.575 98.810 44.600 98.820 ;
        RECT 42.435 98.620 44.600 98.810 ;
        RECT 42.435 98.470 43.370 98.620 ;
        RECT 44.075 98.490 44.600 98.620 ;
        RECT 42.095 97.920 42.765 98.235 ;
        RECT 42.095 96.210 42.265 97.920 ;
        RECT 42.995 97.910 43.370 98.470 ;
        RECT 43.575 97.740 43.905 98.450 ;
        RECT 44.815 98.225 44.985 98.990 ;
        RECT 44.285 98.015 44.985 98.225 ;
        RECT 42.565 97.570 44.535 97.740 ;
        RECT 42.565 96.855 42.735 97.570 ;
        RECT 42.905 97.080 44.195 97.400 ;
        RECT 43.865 96.935 44.195 97.080 ;
        RECT 44.365 96.955 44.535 97.570 ;
        RECT 42.935 96.720 43.655 96.910 ;
        RECT 42.435 96.550 42.765 96.630 ;
        RECT 44.365 96.550 44.535 96.785 ;
        RECT 42.435 96.380 44.535 96.550 ;
        RECT 42.095 96.040 43.065 96.210 ;
        RECT 43.325 96.040 43.655 96.210 ;
        RECT 42.095 94.135 42.265 96.040 ;
        RECT 43.325 95.870 43.585 96.040 ;
        RECT 43.835 95.920 44.135 96.380 ;
        RECT 44.815 96.200 44.985 98.015 ;
        RECT 42.540 95.700 43.585 95.870 ;
        RECT 43.805 95.720 44.135 95.920 ;
        RECT 44.315 95.830 44.985 96.200 ;
        RECT 42.540 94.765 42.710 95.700 ;
        RECT 42.880 95.170 43.245 95.530 ;
        RECT 43.415 95.510 43.585 95.700 ;
        RECT 43.415 95.340 44.535 95.510 ;
        RECT 42.880 95.000 44.165 95.170 ;
        RECT 43.180 94.590 43.775 94.830 ;
        RECT 43.945 94.645 44.165 95.000 ;
        RECT 44.365 94.835 44.535 95.340 ;
        RECT 42.435 94.420 42.990 94.555 ;
        RECT 44.365 94.475 44.535 94.640 ;
        RECT 44.095 94.420 44.535 94.475 ;
        RECT 42.435 94.305 44.535 94.420 ;
        RECT 42.860 94.250 44.225 94.305 ;
        RECT 44.815 94.135 44.985 95.830 ;
        RECT 42.095 93.870 42.725 94.135 ;
        RECT 42.095 93.275 42.265 93.870 ;
        RECT 43.235 93.800 44.185 94.080 ;
        RECT 44.355 93.885 44.985 94.135 ;
        RECT 42.435 93.445 44.555 93.630 ;
        RECT 44.815 93.275 44.985 93.885 ;
        RECT 42.095 92.945 42.765 93.275 ;
        RECT 42.935 93.040 44.265 93.270 ;
        RECT 42.095 92.430 42.265 92.945 ;
        RECT 42.935 92.775 43.105 93.040 ;
        RECT 42.435 92.605 43.105 92.775 ;
        RECT 43.275 92.520 43.925 92.870 ;
        RECT 44.095 92.775 44.265 93.040 ;
        RECT 44.435 92.945 44.985 93.275 ;
        RECT 44.095 92.605 44.555 92.775 ;
        RECT 44.815 92.430 44.985 92.945 ;
        RECT 42.095 90.065 42.265 90.660 ;
        RECT 42.435 90.335 44.645 90.570 ;
        RECT 42.435 90.235 43.420 90.335 ;
        RECT 43.990 90.315 44.645 90.335 ;
        RECT 42.095 89.850 43.405 90.065 ;
        RECT 42.095 88.640 42.265 89.850 ;
        RECT 43.575 89.660 43.905 90.165 ;
        RECT 44.815 90.145 44.985 90.660 ;
        RECT 44.355 89.825 44.985 90.145 ;
        RECT 42.455 89.590 43.905 89.660 ;
        RECT 42.455 89.390 44.555 89.590 ;
        RECT 42.455 89.330 43.185 89.390 ;
        RECT 44.285 89.340 44.555 89.390 ;
        RECT 43.325 89.150 44.160 89.220 ;
        RECT 43.325 89.140 44.595 89.150 ;
        RECT 42.480 89.030 44.595 89.140 ;
        RECT 42.480 88.985 43.455 89.030 ;
        RECT 42.480 88.810 43.405 88.985 ;
        RECT 44.035 88.975 44.595 89.030 ;
        RECT 42.095 88.470 43.275 88.640 ;
        RECT 42.095 87.725 42.265 88.470 ;
        RECT 43.575 88.310 43.905 88.860 ;
        RECT 44.075 88.820 44.595 88.975 ;
        RECT 44.815 88.650 44.985 89.825 ;
        RECT 44.205 88.480 44.985 88.650 ;
        RECT 43.575 88.300 44.600 88.310 ;
        RECT 42.435 88.110 44.600 88.300 ;
        RECT 42.435 87.960 43.370 88.110 ;
        RECT 44.075 87.980 44.600 88.110 ;
        RECT 42.095 87.410 42.765 87.725 ;
        RECT 42.095 85.700 42.265 87.410 ;
        RECT 42.995 87.400 43.370 87.960 ;
        RECT 43.575 87.230 43.905 87.940 ;
        RECT 44.815 87.715 44.985 88.480 ;
        RECT 44.285 87.505 44.985 87.715 ;
        RECT 42.565 87.060 44.535 87.230 ;
        RECT 42.565 86.345 42.735 87.060 ;
        RECT 42.905 86.570 44.195 86.890 ;
        RECT 43.865 86.425 44.195 86.570 ;
        RECT 44.365 86.445 44.535 87.060 ;
        RECT 42.935 86.210 43.655 86.400 ;
        RECT 42.435 86.040 42.765 86.120 ;
        RECT 44.365 86.040 44.535 86.275 ;
        RECT 42.435 85.870 44.535 86.040 ;
        RECT 42.095 85.530 43.065 85.700 ;
        RECT 43.325 85.530 43.655 85.700 ;
        RECT 42.095 83.625 42.265 85.530 ;
        RECT 43.325 85.360 43.585 85.530 ;
        RECT 43.835 85.410 44.135 85.870 ;
        RECT 44.815 85.690 44.985 87.505 ;
        RECT 42.540 85.190 43.585 85.360 ;
        RECT 43.805 85.210 44.135 85.410 ;
        RECT 44.315 85.320 44.985 85.690 ;
        RECT 42.540 84.255 42.710 85.190 ;
        RECT 42.880 84.660 43.245 85.020 ;
        RECT 43.415 85.000 43.585 85.190 ;
        RECT 43.415 84.830 44.535 85.000 ;
        RECT 42.880 84.490 44.165 84.660 ;
        RECT 43.180 84.080 43.775 84.320 ;
        RECT 43.945 84.135 44.165 84.490 ;
        RECT 44.365 84.325 44.535 84.830 ;
        RECT 42.435 83.910 42.990 84.045 ;
        RECT 44.365 83.965 44.535 84.130 ;
        RECT 44.095 83.910 44.535 83.965 ;
        RECT 42.435 83.795 44.535 83.910 ;
        RECT 42.860 83.740 44.225 83.795 ;
        RECT 44.815 83.625 44.985 85.320 ;
        RECT 42.095 83.360 42.725 83.625 ;
        RECT 42.095 82.765 42.265 83.360 ;
        RECT 43.235 83.290 44.185 83.570 ;
        RECT 44.355 83.375 44.985 83.625 ;
        RECT 42.435 82.935 44.555 83.120 ;
        RECT 44.815 82.765 44.985 83.375 ;
        RECT 42.095 82.435 42.765 82.765 ;
        RECT 42.935 82.530 44.265 82.760 ;
        RECT 42.095 81.920 42.265 82.435 ;
        RECT 42.935 82.265 43.105 82.530 ;
        RECT 42.435 82.095 43.105 82.265 ;
        RECT 43.275 82.010 43.925 82.360 ;
        RECT 44.095 82.265 44.265 82.530 ;
        RECT 44.435 82.435 44.985 82.765 ;
        RECT 44.095 82.095 44.555 82.265 ;
        RECT 44.815 81.920 44.985 82.435 ;
        RECT 42.095 81.305 42.265 81.390 ;
        RECT 44.815 81.305 44.985 81.390 ;
        RECT 42.095 81.015 43.430 81.305 ;
        RECT 44.090 81.015 44.985 81.305 ;
        RECT 42.095 80.930 42.265 81.015 ;
        RECT 44.815 80.930 44.985 81.015 ;
        RECT 42.095 79.575 42.265 80.170 ;
        RECT 42.435 79.845 44.645 80.080 ;
        RECT 42.435 79.745 43.420 79.845 ;
        RECT 43.990 79.825 44.645 79.845 ;
        RECT 42.095 79.360 43.405 79.575 ;
        RECT 42.095 78.150 42.265 79.360 ;
        RECT 43.575 79.170 43.905 79.675 ;
        RECT 44.815 79.655 44.985 80.170 ;
        RECT 44.355 79.335 44.985 79.655 ;
        RECT 42.455 79.100 43.905 79.170 ;
        RECT 42.455 78.900 44.555 79.100 ;
        RECT 42.455 78.840 43.185 78.900 ;
        RECT 44.285 78.850 44.555 78.900 ;
        RECT 43.325 78.660 44.160 78.730 ;
        RECT 43.325 78.650 44.595 78.660 ;
        RECT 42.480 78.540 44.595 78.650 ;
        RECT 42.480 78.495 43.455 78.540 ;
        RECT 42.480 78.320 43.405 78.495 ;
        RECT 44.035 78.485 44.595 78.540 ;
        RECT 42.095 77.980 43.275 78.150 ;
        RECT 42.095 77.235 42.265 77.980 ;
        RECT 43.575 77.820 43.905 78.370 ;
        RECT 44.075 78.330 44.595 78.485 ;
        RECT 44.815 78.160 44.985 79.335 ;
        RECT 44.205 77.990 44.985 78.160 ;
        RECT 43.575 77.810 44.600 77.820 ;
        RECT 42.435 77.620 44.600 77.810 ;
        RECT 42.435 77.470 43.370 77.620 ;
        RECT 44.075 77.490 44.600 77.620 ;
        RECT 42.095 76.920 42.765 77.235 ;
        RECT 42.095 75.210 42.265 76.920 ;
        RECT 42.995 76.910 43.370 77.470 ;
        RECT 43.575 76.740 43.905 77.450 ;
        RECT 44.815 77.225 44.985 77.990 ;
        RECT 44.285 77.015 44.985 77.225 ;
        RECT 42.565 76.570 44.535 76.740 ;
        RECT 42.565 75.855 42.735 76.570 ;
        RECT 42.905 76.080 44.195 76.400 ;
        RECT 43.865 75.935 44.195 76.080 ;
        RECT 44.365 75.955 44.535 76.570 ;
        RECT 42.935 75.720 43.655 75.910 ;
        RECT 42.435 75.550 42.765 75.630 ;
        RECT 44.365 75.550 44.535 75.785 ;
        RECT 42.435 75.380 44.535 75.550 ;
        RECT 42.095 75.040 43.065 75.210 ;
        RECT 43.325 75.040 43.655 75.210 ;
        RECT 42.095 73.135 42.265 75.040 ;
        RECT 43.325 74.870 43.585 75.040 ;
        RECT 43.835 74.920 44.135 75.380 ;
        RECT 44.815 75.200 44.985 77.015 ;
        RECT 42.540 74.700 43.585 74.870 ;
        RECT 43.805 74.720 44.135 74.920 ;
        RECT 44.315 74.830 44.985 75.200 ;
        RECT 42.540 73.765 42.710 74.700 ;
        RECT 42.880 74.170 43.245 74.530 ;
        RECT 43.415 74.510 43.585 74.700 ;
        RECT 43.415 74.340 44.535 74.510 ;
        RECT 42.880 74.000 44.165 74.170 ;
        RECT 43.180 73.590 43.775 73.830 ;
        RECT 43.945 73.645 44.165 74.000 ;
        RECT 44.365 73.835 44.535 74.340 ;
        RECT 42.435 73.420 42.990 73.555 ;
        RECT 44.365 73.475 44.535 73.640 ;
        RECT 44.095 73.420 44.535 73.475 ;
        RECT 42.435 73.305 44.535 73.420 ;
        RECT 42.860 73.250 44.225 73.305 ;
        RECT 44.815 73.135 44.985 74.830 ;
        RECT 42.095 72.870 42.725 73.135 ;
        RECT 42.095 72.275 42.265 72.870 ;
        RECT 43.235 72.800 44.185 73.080 ;
        RECT 44.355 72.885 44.985 73.135 ;
        RECT 42.435 72.445 44.555 72.630 ;
        RECT 44.815 72.275 44.985 72.885 ;
        RECT 42.095 71.945 42.765 72.275 ;
        RECT 42.935 72.040 44.265 72.270 ;
        RECT 42.095 71.430 42.265 71.945 ;
        RECT 42.935 71.775 43.105 72.040 ;
        RECT 42.435 71.605 43.105 71.775 ;
        RECT 43.275 71.520 43.925 71.870 ;
        RECT 44.095 71.775 44.265 72.040 ;
        RECT 44.435 71.945 44.985 72.275 ;
        RECT 44.095 71.605 44.555 71.775 ;
        RECT 44.815 71.430 44.985 71.945 ;
        RECT 42.095 69.065 42.265 69.660 ;
        RECT 42.435 69.335 44.645 69.570 ;
        RECT 42.435 69.235 43.420 69.335 ;
        RECT 43.990 69.315 44.645 69.335 ;
        RECT 42.095 68.850 43.405 69.065 ;
        RECT 42.095 67.640 42.265 68.850 ;
        RECT 43.575 68.660 43.905 69.165 ;
        RECT 44.815 69.145 44.985 69.660 ;
        RECT 44.355 68.825 44.985 69.145 ;
        RECT 42.455 68.590 43.905 68.660 ;
        RECT 42.455 68.390 44.555 68.590 ;
        RECT 42.455 68.330 43.185 68.390 ;
        RECT 44.285 68.340 44.555 68.390 ;
        RECT 43.325 68.150 44.160 68.220 ;
        RECT 43.325 68.140 44.595 68.150 ;
        RECT 42.480 68.030 44.595 68.140 ;
        RECT 42.480 67.985 43.455 68.030 ;
        RECT 42.480 67.810 43.405 67.985 ;
        RECT 44.035 67.975 44.595 68.030 ;
        RECT 42.095 67.470 43.275 67.640 ;
        RECT 42.095 66.725 42.265 67.470 ;
        RECT 43.575 67.310 43.905 67.860 ;
        RECT 44.075 67.820 44.595 67.975 ;
        RECT 44.815 67.650 44.985 68.825 ;
        RECT 44.205 67.480 44.985 67.650 ;
        RECT 43.575 67.300 44.600 67.310 ;
        RECT 42.435 67.110 44.600 67.300 ;
        RECT 42.435 66.960 43.370 67.110 ;
        RECT 44.075 66.980 44.600 67.110 ;
        RECT 42.095 66.410 42.765 66.725 ;
        RECT 42.095 64.700 42.265 66.410 ;
        RECT 42.995 66.400 43.370 66.960 ;
        RECT 43.575 66.230 43.905 66.940 ;
        RECT 44.815 66.715 44.985 67.480 ;
        RECT 44.285 66.505 44.985 66.715 ;
        RECT 42.565 66.060 44.535 66.230 ;
        RECT 42.565 65.345 42.735 66.060 ;
        RECT 42.905 65.570 44.195 65.890 ;
        RECT 43.865 65.425 44.195 65.570 ;
        RECT 44.365 65.445 44.535 66.060 ;
        RECT 42.935 65.210 43.655 65.400 ;
        RECT 42.435 65.040 42.765 65.120 ;
        RECT 44.365 65.040 44.535 65.275 ;
        RECT 42.435 64.870 44.535 65.040 ;
        RECT 42.095 64.530 43.065 64.700 ;
        RECT 43.325 64.530 43.655 64.700 ;
        RECT 42.095 62.625 42.265 64.530 ;
        RECT 43.325 64.360 43.585 64.530 ;
        RECT 43.835 64.410 44.135 64.870 ;
        RECT 44.815 64.690 44.985 66.505 ;
        RECT 42.540 64.190 43.585 64.360 ;
        RECT 43.805 64.210 44.135 64.410 ;
        RECT 44.315 64.320 44.985 64.690 ;
        RECT 42.540 63.255 42.710 64.190 ;
        RECT 42.880 63.660 43.245 64.020 ;
        RECT 43.415 64.000 43.585 64.190 ;
        RECT 43.415 63.830 44.535 64.000 ;
        RECT 42.880 63.490 44.165 63.660 ;
        RECT 43.180 63.080 43.775 63.320 ;
        RECT 43.945 63.135 44.165 63.490 ;
        RECT 44.365 63.325 44.535 63.830 ;
        RECT 42.435 62.910 42.990 63.045 ;
        RECT 44.365 62.965 44.535 63.130 ;
        RECT 44.095 62.910 44.535 62.965 ;
        RECT 42.435 62.795 44.535 62.910 ;
        RECT 42.860 62.740 44.225 62.795 ;
        RECT 44.815 62.625 44.985 64.320 ;
        RECT 42.095 62.360 42.725 62.625 ;
        RECT 42.095 61.765 42.265 62.360 ;
        RECT 43.235 62.290 44.185 62.570 ;
        RECT 44.355 62.375 44.985 62.625 ;
        RECT 42.435 61.935 44.555 62.120 ;
        RECT 44.815 61.765 44.985 62.375 ;
        RECT 42.095 61.435 42.765 61.765 ;
        RECT 42.935 61.530 44.265 61.760 ;
        RECT 42.095 60.920 42.265 61.435 ;
        RECT 42.935 61.265 43.105 61.530 ;
        RECT 42.435 61.095 43.105 61.265 ;
        RECT 43.275 61.010 43.925 61.360 ;
        RECT 44.095 61.265 44.265 61.530 ;
        RECT 44.435 61.435 44.985 61.765 ;
        RECT 44.095 61.095 44.555 61.265 ;
        RECT 44.815 60.920 44.985 61.435 ;
        RECT 42.095 60.205 42.265 60.290 ;
        RECT 44.815 60.205 44.985 60.290 ;
        RECT 42.095 59.915 43.430 60.205 ;
        RECT 44.090 59.915 44.985 60.205 ;
        RECT 42.095 59.595 42.265 59.915 ;
        RECT 44.815 59.595 44.985 59.915 ;
        RECT 42.095 59.265 43.415 59.595 ;
        RECT 44.015 59.265 44.985 59.595 ;
        RECT 42.095 58.755 42.265 59.265 ;
        RECT 42.435 58.925 44.645 59.095 ;
        RECT 42.095 58.425 43.065 58.755 ;
        RECT 43.285 58.600 44.165 58.925 ;
        RECT 44.815 58.755 44.985 59.265 ;
        RECT 42.095 57.905 42.265 58.425 ;
        RECT 43.285 58.255 43.455 58.600 ;
        RECT 42.435 58.085 43.455 58.255 ;
        RECT 43.995 58.255 44.165 58.600 ;
        RECT 44.335 58.425 44.985 58.755 ;
        RECT 42.095 57.665 43.065 57.905 ;
        RECT 43.655 57.880 43.825 58.210 ;
        RECT 43.995 58.085 44.645 58.255 ;
        RECT 43.245 57.710 44.165 57.880 ;
        RECT 44.815 57.835 44.985 58.425 ;
        RECT 42.095 57.070 42.265 57.665 ;
        RECT 43.245 57.495 43.415 57.710 ;
        RECT 42.435 57.165 43.415 57.495 ;
        RECT 43.585 57.160 43.825 57.540 ;
        RECT 43.995 57.415 44.165 57.710 ;
        RECT 44.335 57.595 44.985 57.835 ;
        RECT 43.995 57.245 44.645 57.415 ;
        RECT 44.815 57.070 44.985 57.595 ;
        RECT 128.490 37.000 130.590 37.170 ;
        RECT 128.490 36.270 128.660 37.000 ;
        RECT 129.290 36.485 129.790 36.655 ;
        RECT 128.490 32.230 129.230 36.270 ;
        RECT 129.850 32.230 130.020 36.270 ;
        RECT 128.490 31.860 128.660 32.230 ;
        RECT 130.420 31.860 130.590 37.000 ;
        RECT 128.490 31.690 130.590 31.860 ;
        RECT 130.890 35.000 132.640 35.170 ;
        RECT 130.890 31.860 131.060 35.000 ;
        RECT 131.600 34.485 131.930 34.655 ;
        RECT 131.460 32.230 131.630 34.270 ;
        RECT 131.900 32.230 132.070 34.270 ;
        RECT 132.470 31.860 132.640 35.000 ;
        RECT 133.235 34.950 134.985 35.120 ;
        RECT 133.235 32.860 133.405 34.950 ;
        RECT 133.945 34.440 134.275 34.610 ;
        RECT 133.805 33.230 133.975 34.270 ;
        RECT 134.245 33.230 134.415 34.270 ;
        RECT 134.815 32.860 134.985 34.950 ;
        RECT 133.235 32.690 134.985 32.860 ;
        RECT 135.290 34.950 137.390 35.120 ;
        RECT 130.890 31.690 132.640 31.860 ;
        RECT 135.290 31.860 135.460 34.950 ;
        RECT 136.090 34.440 136.590 34.610 ;
        RECT 137.220 34.270 137.390 34.950 ;
        RECT 135.860 32.230 136.030 34.270 ;
        RECT 136.650 32.230 137.390 34.270 ;
        RECT 137.220 31.860 137.390 32.230 ;
        RECT 135.290 31.690 137.390 31.860 ;
        RECT 128.485 31.195 130.585 31.365 ;
        RECT 128.485 30.465 128.655 31.195 ;
        RECT 129.285 30.680 129.785 30.850 ;
        RECT 128.485 26.425 129.225 30.465 ;
        RECT 129.845 26.425 130.015 30.465 ;
        RECT 128.485 26.055 128.655 26.425 ;
        RECT 130.415 26.055 130.585 31.195 ;
        RECT 128.485 25.885 130.585 26.055 ;
        RECT 130.885 29.195 132.635 29.365 ;
        RECT 130.885 26.055 131.055 29.195 ;
        RECT 131.595 28.680 131.925 28.850 ;
        RECT 131.455 26.425 131.625 28.465 ;
        RECT 131.895 26.425 132.065 28.465 ;
        RECT 132.465 26.055 132.635 29.195 ;
        RECT 133.230 29.145 134.980 29.315 ;
        RECT 133.230 27.055 133.400 29.145 ;
        RECT 133.940 28.635 134.270 28.805 ;
        RECT 133.800 27.425 133.970 28.465 ;
        RECT 134.240 27.425 134.410 28.465 ;
        RECT 134.810 27.055 134.980 29.145 ;
        RECT 133.230 26.885 134.980 27.055 ;
        RECT 135.285 29.145 137.385 29.315 ;
        RECT 130.885 25.885 132.635 26.055 ;
        RECT 135.285 26.055 135.455 29.145 ;
        RECT 136.085 28.635 136.585 28.805 ;
        RECT 137.215 28.465 137.385 29.145 ;
        RECT 135.855 26.425 136.025 28.465 ;
        RECT 136.645 26.425 137.385 28.465 ;
        RECT 137.215 26.055 137.385 26.425 ;
        RECT 135.285 25.885 137.385 26.055 ;
        RECT 143.365 27.925 146.845 28.095 ;
        RECT 143.365 26.165 143.535 27.925 ;
        RECT 143.905 27.355 145.945 27.925 ;
        RECT 146.160 26.795 146.330 27.295 ;
        RECT 143.905 26.565 145.945 26.735 ;
        RECT 146.675 26.165 146.845 27.925 ;
        RECT 143.365 25.995 146.845 26.165 ;
        RECT 147.145 27.925 150.625 28.095 ;
        RECT 147.145 26.165 147.315 27.925 ;
        RECT 148.045 27.355 150.085 27.925 ;
        RECT 147.660 26.795 147.830 27.295 ;
        RECT 148.045 26.565 150.085 26.735 ;
        RECT 150.455 26.165 150.625 27.925 ;
        RECT 147.145 25.995 150.625 26.165 ;
        RECT 128.485 25.400 130.585 25.570 ;
        RECT 128.485 24.670 128.655 25.400 ;
        RECT 129.285 24.885 129.785 25.055 ;
        RECT 128.485 20.630 129.225 24.670 ;
        RECT 129.845 20.630 130.015 24.670 ;
        RECT 128.485 20.260 128.655 20.630 ;
        RECT 130.415 20.260 130.585 25.400 ;
        RECT 143.815 24.720 146.245 24.890 ;
        RECT 128.485 20.090 130.585 20.260 ;
        RECT 130.885 23.400 132.635 23.570 ;
        RECT 130.885 20.260 131.055 23.400 ;
        RECT 131.595 22.885 131.925 23.055 ;
        RECT 131.455 20.630 131.625 22.670 ;
        RECT 131.895 20.630 132.065 22.670 ;
        RECT 132.465 20.260 132.635 23.400 ;
        RECT 133.230 23.350 134.980 23.520 ;
        RECT 133.230 21.260 133.400 23.350 ;
        RECT 133.940 22.840 134.270 23.010 ;
        RECT 133.800 21.630 133.970 22.670 ;
        RECT 134.240 21.630 134.410 22.670 ;
        RECT 134.810 21.260 134.980 23.350 ;
        RECT 133.230 21.090 134.980 21.260 ;
        RECT 135.285 23.350 137.385 23.520 ;
        RECT 130.885 20.090 132.635 20.260 ;
        RECT 135.285 20.260 135.455 23.350 ;
        RECT 136.085 22.840 136.585 23.010 ;
        RECT 137.215 22.670 137.385 23.350 ;
        RECT 143.815 22.960 143.985 24.720 ;
        RECT 144.355 24.150 145.395 24.320 ;
        RECT 145.565 23.590 145.735 24.090 ;
        RECT 144.355 23.490 145.395 23.530 ;
        RECT 144.350 22.960 145.400 23.490 ;
        RECT 146.075 22.960 146.245 24.720 ;
        RECT 143.815 22.790 146.245 22.960 ;
        RECT 147.950 24.715 150.380 24.885 ;
        RECT 147.950 22.955 148.120 24.715 ;
        RECT 148.490 24.145 149.530 24.315 ;
        RECT 149.700 23.585 149.870 24.085 ;
        RECT 148.490 22.955 149.530 23.525 ;
        RECT 150.210 22.955 150.380 24.715 ;
        RECT 147.950 22.785 150.380 22.955 ;
        RECT 135.855 20.630 136.025 22.670 ;
        RECT 136.645 20.630 137.385 22.670 ;
        RECT 137.215 20.260 137.385 20.630 ;
        RECT 135.285 20.090 137.385 20.260 ;
        RECT 128.490 19.600 130.590 19.770 ;
        RECT 128.490 18.870 128.660 19.600 ;
        RECT 129.290 19.085 129.790 19.255 ;
        RECT 128.490 14.830 129.230 18.870 ;
        RECT 129.850 14.830 130.020 18.870 ;
        RECT 128.490 14.460 128.660 14.830 ;
        RECT 130.420 14.460 130.590 19.600 ;
        RECT 128.490 14.290 130.590 14.460 ;
        RECT 130.890 17.600 132.640 17.770 ;
        RECT 130.890 14.460 131.060 17.600 ;
        RECT 131.600 17.085 131.930 17.255 ;
        RECT 131.460 14.830 131.630 16.870 ;
        RECT 131.900 14.830 132.070 16.870 ;
        RECT 132.470 14.460 132.640 17.600 ;
        RECT 133.235 17.550 134.985 17.720 ;
        RECT 133.235 15.460 133.405 17.550 ;
        RECT 133.945 17.040 134.275 17.210 ;
        RECT 133.805 15.830 133.975 16.870 ;
        RECT 134.245 15.830 134.415 16.870 ;
        RECT 134.815 15.460 134.985 17.550 ;
        RECT 133.235 15.290 134.985 15.460 ;
        RECT 135.290 17.550 137.390 17.720 ;
        RECT 130.890 14.290 132.640 14.460 ;
        RECT 135.290 14.460 135.460 17.550 ;
        RECT 136.090 17.040 136.590 17.210 ;
        RECT 137.220 16.870 137.390 17.550 ;
        RECT 135.860 14.830 136.030 16.870 ;
        RECT 136.650 14.830 137.390 16.870 ;
        RECT 137.220 14.460 137.390 14.830 ;
        RECT 135.290 14.290 137.390 14.460 ;
        RECT 128.485 13.800 130.585 13.970 ;
        RECT 128.485 13.070 128.655 13.800 ;
        RECT 129.285 13.285 129.785 13.455 ;
        RECT 128.485 9.030 129.225 13.070 ;
        RECT 129.845 9.030 130.015 13.070 ;
        RECT 128.485 8.660 128.655 9.030 ;
        RECT 130.415 8.660 130.585 13.800 ;
        RECT 128.485 8.490 130.585 8.660 ;
        RECT 130.885 11.800 132.635 11.970 ;
        RECT 130.885 8.660 131.055 11.800 ;
        RECT 131.595 11.285 131.925 11.455 ;
        RECT 131.455 9.030 131.625 11.070 ;
        RECT 131.895 9.030 132.065 11.070 ;
        RECT 132.465 8.660 132.635 11.800 ;
        RECT 133.230 11.750 134.980 11.920 ;
        RECT 133.230 9.660 133.400 11.750 ;
        RECT 133.940 11.240 134.270 11.410 ;
        RECT 133.800 10.030 133.970 11.070 ;
        RECT 134.240 10.030 134.410 11.070 ;
        RECT 134.810 9.660 134.980 11.750 ;
        RECT 133.230 9.490 134.980 9.660 ;
        RECT 135.285 11.750 137.385 11.920 ;
        RECT 130.885 8.490 132.635 8.660 ;
        RECT 135.285 8.660 135.455 11.750 ;
        RECT 136.085 11.240 136.585 11.410 ;
        RECT 137.215 11.070 137.385 11.750 ;
        RECT 135.855 9.030 136.025 11.070 ;
        RECT 136.645 9.030 137.385 11.070 ;
        RECT 137.215 8.660 137.385 9.030 ;
        RECT 135.285 8.490 137.385 8.660 ;
        RECT 131.325 5.735 131.495 6.330 ;
        RECT 131.665 5.905 132.645 6.235 ;
        RECT 131.325 5.495 132.295 5.735 ;
        RECT 132.475 5.690 132.645 5.905 ;
        RECT 132.815 5.860 133.055 6.240 ;
        RECT 133.225 5.985 133.875 6.155 ;
        RECT 133.225 5.690 133.395 5.985 ;
        RECT 134.045 5.805 134.215 6.330 ;
        RECT 132.475 5.520 133.395 5.690 ;
        RECT 133.565 5.565 134.215 5.805 ;
        RECT 131.325 4.975 131.495 5.495 ;
        RECT 131.665 5.145 132.685 5.315 ;
        RECT 132.885 5.190 133.055 5.520 ;
        RECT 131.325 4.645 132.295 4.975 ;
        RECT 132.515 4.800 132.685 5.145 ;
        RECT 133.225 5.145 133.875 5.315 ;
        RECT 133.225 4.800 133.395 5.145 ;
        RECT 134.045 4.975 134.215 5.565 ;
        RECT 131.325 4.135 131.495 4.645 ;
        RECT 132.515 4.475 133.395 4.800 ;
        RECT 133.565 4.645 134.215 4.975 ;
        RECT 131.665 4.305 133.875 4.475 ;
        RECT 134.045 4.135 134.215 4.645 ;
        RECT 131.325 3.805 132.645 4.135 ;
        RECT 133.245 3.805 134.215 4.135 ;
        RECT 131.325 3.485 131.495 3.805 ;
        RECT 134.045 3.485 134.215 3.805 ;
        RECT 131.325 3.195 132.660 3.485 ;
        RECT 133.320 3.195 134.215 3.485 ;
        RECT 131.325 3.110 131.495 3.195 ;
        RECT 134.045 3.110 134.215 3.195 ;
      LAYER met1 ;
        RECT 83.310 222.740 84.170 224.200 ;
        RECT 82.010 222.260 85.230 222.740 ;
        RECT 80.900 221.400 81.500 221.600 ;
        RECT 82.050 221.400 82.400 221.455 ;
        RECT 80.900 221.200 82.400 221.400 ;
        RECT 80.900 221.000 81.500 221.200 ;
        RECT 82.050 221.155 82.400 221.200 ;
        RECT 83.450 221.420 83.800 221.455 ;
        RECT 85.500 221.420 85.940 221.520 ;
        RECT 83.450 221.220 85.940 221.420 ;
        RECT 83.450 221.155 83.800 221.220 ;
        RECT 85.500 221.100 85.940 221.220 ;
        RECT 109.000 220.350 109.500 220.850 ;
        RECT 82.010 219.540 85.290 220.020 ;
        RECT 83.340 218.080 84.200 219.540 ;
        RECT 141.650 217.500 142.520 218.400 ;
        RECT 141.850 216.160 142.350 217.500 ;
        RECT 79.990 216.130 81.300 216.140 ;
        RECT 79.990 216.120 84.010 216.130 ;
        RECT 111.920 216.120 116.125 216.160 ;
        RECT 79.990 216.000 85.345 216.120 ;
        RECT 79.990 214.800 85.390 216.000 ;
        RECT 110.235 214.850 116.125 216.120 ;
        RECT 141.015 214.850 143.120 216.160 ;
        RECT 110.235 214.810 114.610 214.850 ;
        RECT 79.990 214.035 81.300 214.800 ;
        RECT 83.250 209.540 85.390 214.800 ;
        RECT 114.010 212.975 116.115 213.100 ;
        RECT 141.005 212.990 143.110 213.100 ;
        RECT 110.780 211.885 116.115 212.975 ;
        RECT 110.780 210.040 111.870 211.885 ;
        RECT 114.010 211.790 116.115 211.885 ;
        RECT 83.280 208.730 85.385 209.540 ;
        RECT 110.275 208.730 112.380 210.040 ;
        RECT 114.010 208.730 116.115 210.040 ;
        RECT 141.000 209.040 143.120 212.990 ;
        RECT 141.005 208.730 143.110 209.040 ;
        RECT 110.750 207.635 111.840 208.730 ;
        RECT 114.230 208.670 115.000 208.730 ;
        RECT 114.500 207.700 115.000 208.670 ;
        RECT 83.715 206.545 111.840 207.635 ;
        RECT 114.330 206.800 115.200 207.700 ;
        RECT 83.715 202.660 84.805 206.545 ;
        RECT 114.100 205.595 116.205 205.720 ;
        RECT 141.095 205.610 143.200 205.720 ;
        RECT 110.870 204.505 116.205 205.595 ;
        RECT 110.870 202.660 111.960 204.505 ;
        RECT 114.100 204.410 116.205 204.505 ;
        RECT 83.370 201.350 85.475 202.660 ;
        RECT 110.365 201.350 112.470 202.660 ;
        RECT 114.100 201.350 116.205 202.660 ;
        RECT 141.090 201.660 143.210 205.610 ;
        RECT 141.095 201.350 143.200 201.660 ;
        RECT 110.480 200.305 111.570 201.350 ;
        RECT 83.445 199.215 111.570 200.305 ;
        RECT 114.500 200.210 115.000 201.350 ;
        RECT 114.500 200.200 115.010 200.210 ;
        RECT 114.330 199.300 115.200 200.200 ;
        RECT 83.445 195.330 84.535 199.215 ;
        RECT 113.830 198.265 115.935 198.390 ;
        RECT 140.825 198.280 142.930 198.390 ;
        RECT 110.600 197.175 115.935 198.265 ;
        RECT 110.600 195.330 111.690 197.175 ;
        RECT 113.830 197.080 115.935 197.175 ;
        RECT 83.100 194.020 85.205 195.330 ;
        RECT 110.095 194.020 112.200 195.330 ;
        RECT 113.830 194.020 115.935 195.330 ;
        RECT 140.820 194.330 142.940 198.280 ;
        RECT 140.825 194.020 142.930 194.330 ;
        RECT 110.570 192.925 111.660 194.020 ;
        RECT 83.535 191.835 111.660 192.925 ;
        RECT 114.500 192.700 115.000 194.020 ;
        RECT 79.990 183.205 81.300 189.145 ;
        RECT 83.535 187.950 84.625 191.835 ;
        RECT 114.330 191.800 115.200 192.700 ;
        RECT 113.920 190.885 116.025 191.010 ;
        RECT 140.915 190.900 143.020 191.010 ;
        RECT 110.690 189.795 116.025 190.885 ;
        RECT 110.690 187.950 111.780 189.795 ;
        RECT 113.920 189.700 116.025 189.795 ;
        RECT 83.190 186.640 85.295 187.950 ;
        RECT 110.185 186.640 112.290 187.950 ;
        RECT 113.920 186.640 116.025 187.950 ;
        RECT 140.910 186.950 143.030 190.900 ;
        RECT 140.915 186.640 143.020 186.950 ;
        RECT 110.610 185.515 111.700 186.640 ;
        RECT 114.510 185.700 115.010 186.640 ;
        RECT 83.575 184.425 111.700 185.515 ;
        RECT 114.330 184.800 115.200 185.700 ;
        RECT 83.575 180.540 84.665 184.425 ;
        RECT 113.960 183.475 116.065 183.600 ;
        RECT 140.955 183.490 143.060 183.600 ;
        RECT 110.730 182.385 116.065 183.475 ;
        RECT 110.730 180.540 111.820 182.385 ;
        RECT 113.960 182.290 116.065 182.385 ;
        RECT 83.230 179.230 85.335 180.540 ;
        RECT 110.225 179.230 112.330 180.540 ;
        RECT 113.960 179.230 116.065 180.540 ;
        RECT 140.950 179.540 143.070 183.490 ;
        RECT 140.955 179.230 143.060 179.540 ;
        RECT 110.700 178.135 111.790 179.230 ;
        RECT 114.230 179.170 115.610 179.230 ;
        RECT 114.510 178.200 115.010 179.170 ;
        RECT 83.665 177.045 111.790 178.135 ;
        RECT 114.330 177.300 115.200 178.200 ;
        RECT 83.665 173.160 84.755 177.045 ;
        RECT 114.050 176.095 116.155 176.220 ;
        RECT 141.045 176.110 143.150 176.220 ;
        RECT 110.820 175.005 116.155 176.095 ;
        RECT 110.820 173.160 111.910 175.005 ;
        RECT 114.050 174.910 116.155 175.005 ;
        RECT 83.320 171.850 85.425 173.160 ;
        RECT 110.315 171.850 112.420 173.160 ;
        RECT 114.050 171.850 116.155 173.160 ;
        RECT 141.040 172.160 143.160 176.110 ;
        RECT 141.045 171.850 143.150 172.160 ;
        RECT 110.720 170.705 111.810 171.850 ;
        RECT 83.685 169.615 111.810 170.705 ;
        RECT 114.500 170.700 115.000 171.850 ;
        RECT 114.340 169.800 115.210 170.700 ;
        RECT 83.685 165.730 84.775 169.615 ;
        RECT 114.070 168.665 116.175 168.790 ;
        RECT 141.065 168.680 143.170 168.790 ;
        RECT 110.840 167.575 116.175 168.665 ;
        RECT 110.840 165.730 111.930 167.575 ;
        RECT 114.070 167.480 116.175 167.575 ;
        RECT 83.340 164.420 85.445 165.730 ;
        RECT 110.335 164.420 112.440 165.730 ;
        RECT 114.070 164.420 116.175 165.730 ;
        RECT 141.060 164.730 143.180 168.680 ;
        RECT 141.065 164.420 143.170 164.730 ;
        RECT 110.810 163.800 111.900 164.420 ;
        RECT 110.800 162.720 111.900 163.800 ;
        RECT 114.500 163.200 115.000 164.420 ;
        RECT 96.540 162.270 100.790 162.290 ;
        RECT 96.430 160.185 100.790 162.270 ;
        RECT 110.680 160.615 111.990 162.720 ;
        RECT 114.340 162.300 115.210 163.200 ;
        RECT 96.430 160.165 100.760 160.185 ;
        RECT 96.540 160.140 100.760 160.165 ;
        RECT 79.990 158.170 81.300 158.315 ;
        RECT 79.970 156.210 81.300 158.170 ;
        RECT 79.970 154.490 81.290 156.210 ;
        RECT 76.780 154.030 77.260 154.490 ;
        RECT 79.500 154.030 81.290 154.490 ;
        RECT 79.970 135.260 81.290 154.030 ;
        RECT 96.430 135.260 97.740 135.275 ;
        RECT 79.970 135.250 97.740 135.260 ;
        RECT 77.550 133.170 97.740 135.250 ;
        RECT 99.480 133.190 100.790 135.295 ;
        RECT 103.600 135.010 104.400 135.810 ;
        RECT 77.550 133.160 97.700 133.170 ;
        RECT 77.550 133.150 81.580 133.160 ;
        RECT 77.550 132.750 79.040 133.150 ;
        RECT 77.710 132.740 79.040 132.750 ;
        RECT 99.695 129.510 100.705 133.190 ;
        RECT 103.790 133.150 104.200 135.010 ;
        RECT 110.680 134.010 111.990 135.725 ;
        RECT 110.680 134.000 113.600 134.010 ;
        RECT 103.370 133.005 105.210 133.150 ;
        RECT 108.500 133.010 113.600 134.000 ;
        RECT 103.370 132.855 107.180 133.005 ;
        RECT 108.500 133.000 111.000 133.010 ;
        RECT 103.370 132.670 105.210 132.855 ;
        RECT 107.030 132.350 107.180 132.855 ;
        RECT 106.950 132.050 107.250 132.350 ;
        RECT 102.370 131.530 103.170 131.740 ;
        RECT 108.490 131.720 109.500 133.000 ;
        RECT 112.550 131.820 113.600 133.010 ;
        RECT 104.180 131.530 104.520 131.600 ;
        RECT 102.370 131.240 104.030 131.530 ;
        RECT 102.370 130.940 103.170 131.240 ;
        RECT 104.170 131.230 107.740 131.530 ;
        RECT 107.930 131.490 109.930 131.720 ;
        RECT 112.550 131.490 113.590 131.820 ;
        RECT 114.400 131.530 115.200 131.800 ;
        RECT 107.930 131.050 109.930 131.280 ;
        RECT 112.575 131.160 113.575 131.280 ;
        RECT 113.735 131.250 115.200 131.530 ;
        RECT 113.735 131.240 113.965 131.250 ;
        RECT 112.575 131.050 113.580 131.160 ;
        RECT 102.390 130.430 103.190 130.570 ;
        RECT 102.390 129.950 105.210 130.430 ;
        RECT 102.390 129.770 103.190 129.950 ;
        RECT 108.500 129.510 109.500 131.050 ;
        RECT 111.950 130.360 112.250 130.750 ;
        RECT 111.880 129.970 112.310 130.360 ;
        RECT 112.580 129.510 113.580 131.050 ;
        RECT 114.400 131.000 115.200 131.250 ;
        RECT 99.695 128.500 113.580 129.510 ;
        RECT 109.700 127.020 112.210 128.500 ;
        RECT 44.000 123.400 44.600 124.000 ;
        RECT 41.950 122.170 42.430 123.010 ;
        RECT 43.010 122.200 43.510 122.700 ;
        RECT 41.750 121.890 42.430 122.170 ;
        RECT 43.110 122.050 43.410 122.200 ;
        RECT 41.750 84.000 42.420 121.890 ;
        RECT 43.060 121.750 43.460 122.050 ;
        RECT 44.100 120.300 44.500 123.400 ;
        RECT 44.660 122.820 45.330 123.020 ;
        RECT 44.660 122.470 45.340 122.820 ;
        RECT 43.255 118.105 43.485 118.395 ;
        RECT 42.915 117.670 43.145 117.960 ;
        RECT 42.960 116.390 43.100 117.670 ;
        RECT 42.915 116.100 43.145 116.390 ;
        RECT 42.960 114.290 43.100 116.100 ;
        RECT 43.300 115.875 43.440 118.105 ;
        RECT 43.255 115.585 43.485 115.875 ;
        RECT 43.300 114.685 43.440 115.585 ;
        RECT 43.830 114.770 44.460 115.130 ;
        RECT 43.255 114.395 43.485 114.685 ;
        RECT 42.915 114.000 43.145 114.290 ;
        RECT 43.500 113.000 43.900 113.870 ;
        RECT 43.500 112.600 44.500 113.000 ;
        RECT 43.010 111.690 43.510 112.190 ;
        RECT 43.110 111.540 43.410 111.690 ;
        RECT 43.060 111.240 43.460 111.540 ;
        RECT 44.100 109.800 44.500 112.600 ;
        RECT 43.255 107.595 43.485 107.885 ;
        RECT 42.915 107.160 43.145 107.450 ;
        RECT 42.960 105.880 43.100 107.160 ;
        RECT 42.915 105.590 43.145 105.880 ;
        RECT 42.960 103.780 43.100 105.590 ;
        RECT 43.300 105.365 43.440 107.595 ;
        RECT 43.255 105.075 43.485 105.365 ;
        RECT 43.300 104.175 43.440 105.075 ;
        RECT 43.830 104.260 44.460 104.620 ;
        RECT 43.255 103.885 43.485 104.175 ;
        RECT 42.915 103.490 43.145 103.780 ;
        RECT 43.500 102.500 43.900 103.360 ;
        RECT 43.500 102.100 44.500 102.500 ;
        RECT 43.010 101.200 43.510 101.700 ;
        RECT 43.110 101.050 43.410 101.200 ;
        RECT 43.060 100.750 43.460 101.050 ;
        RECT 44.100 99.300 44.500 102.100 ;
        RECT 43.255 97.105 43.485 97.395 ;
        RECT 42.915 96.670 43.145 96.960 ;
        RECT 42.960 95.390 43.100 96.670 ;
        RECT 42.915 95.100 43.145 95.390 ;
        RECT 42.960 93.290 43.100 95.100 ;
        RECT 43.300 94.875 43.440 97.105 ;
        RECT 43.255 94.585 43.485 94.875 ;
        RECT 43.300 93.685 43.440 94.585 ;
        RECT 43.830 93.770 44.460 94.130 ;
        RECT 43.255 93.395 43.485 93.685 ;
        RECT 42.915 93.000 43.145 93.290 ;
        RECT 43.500 92.000 43.900 92.870 ;
        RECT 43.500 91.600 44.500 92.000 ;
        RECT 43.010 90.690 43.510 91.190 ;
        RECT 43.110 90.540 43.410 90.690 ;
        RECT 43.060 90.240 43.460 90.540 ;
        RECT 44.100 88.800 44.500 91.600 ;
        RECT 44.660 88.000 45.330 122.470 ;
        RECT 49.690 122.250 50.170 122.710 ;
        RECT 52.410 122.250 52.890 122.710 ;
        RECT 43.255 86.595 43.485 86.885 ;
        RECT 42.915 86.160 43.145 86.450 ;
        RECT 42.960 84.880 43.100 86.160 ;
        RECT 42.915 84.590 43.145 84.880 ;
        RECT 36.000 80.500 42.430 84.000 ;
        RECT 42.960 82.780 43.100 84.590 ;
        RECT 43.300 84.365 43.440 86.595 ;
        RECT 44.660 84.500 51.080 88.000 ;
        RECT 43.255 84.075 43.485 84.365 ;
        RECT 43.300 83.175 43.440 84.075 ;
        RECT 43.830 83.260 44.460 83.620 ;
        RECT 43.255 82.885 43.485 83.175 ;
        RECT 42.915 82.490 43.145 82.780 ;
        RECT 43.500 81.500 43.900 82.360 ;
        RECT 43.500 81.100 44.500 81.500 ;
        RECT 38.010 80.490 42.430 80.500 ;
        RECT 41.750 57.070 42.420 80.490 ;
        RECT 43.010 80.200 43.510 80.700 ;
        RECT 43.110 80.050 43.410 80.200 ;
        RECT 43.060 79.750 43.460 80.050 ;
        RECT 44.100 78.300 44.500 81.100 ;
        RECT 43.255 76.105 43.485 76.395 ;
        RECT 42.915 75.670 43.145 75.960 ;
        RECT 42.960 74.390 43.100 75.670 ;
        RECT 42.915 74.100 43.145 74.390 ;
        RECT 42.960 72.290 43.100 74.100 ;
        RECT 43.300 73.875 43.440 76.105 ;
        RECT 43.255 73.585 43.485 73.875 ;
        RECT 43.300 72.685 43.440 73.585 ;
        RECT 43.830 72.770 44.460 73.130 ;
        RECT 43.255 72.395 43.485 72.685 ;
        RECT 42.915 72.000 43.145 72.290 ;
        RECT 43.500 71.000 43.900 71.870 ;
        RECT 43.500 70.600 44.500 71.000 ;
        RECT 43.010 69.690 43.510 70.190 ;
        RECT 43.110 69.540 43.410 69.690 ;
        RECT 43.060 69.240 43.460 69.540 ;
        RECT 44.100 67.800 44.500 70.600 ;
        RECT 43.255 65.595 43.485 65.885 ;
        RECT 42.915 65.160 43.145 65.450 ;
        RECT 42.960 63.880 43.100 65.160 ;
        RECT 42.915 63.590 43.145 63.880 ;
        RECT 42.960 61.780 43.100 63.590 ;
        RECT 43.300 63.365 43.440 65.595 ;
        RECT 43.255 63.075 43.485 63.365 ;
        RECT 43.300 62.175 43.440 63.075 ;
        RECT 43.830 62.260 44.460 62.620 ;
        RECT 43.255 61.885 43.485 62.175 ;
        RECT 42.915 61.490 43.145 61.780 ;
        RECT 43.500 60.470 43.900 61.360 ;
        RECT 43.620 58.860 43.820 60.470 ;
        RECT 43.555 58.510 43.855 58.860 ;
        RECT 43.555 57.110 43.855 57.460 ;
        RECT 43.605 56.400 43.805 57.110 ;
        RECT 44.660 57.070 45.330 84.500 ;
        RECT 43.400 55.800 44.000 56.400 ;
        RECT 130.795 37.620 131.305 37.720 ;
        RECT 129.400 37.320 131.305 37.620 ;
        RECT 129.400 36.685 129.700 37.320 ;
        RECT 130.795 37.220 131.305 37.320 ;
        RECT 129.310 36.455 129.770 36.685 ;
        RECT 136.100 36.520 136.600 37.020 ;
        RECT 136.200 36.500 136.505 36.520 ;
        RECT 126.985 32.250 129.260 36.250 ;
        RECT 129.820 34.250 130.050 36.250 ;
        RECT 132.685 35.790 133.185 36.290 ;
        RECT 136.200 36.220 136.500 36.500 ;
        RECT 132.785 35.490 133.085 35.790 ;
        RECT 131.690 35.340 134.190 35.490 ;
        RECT 131.690 34.685 131.840 35.340 ;
        RECT 131.620 34.455 131.910 34.685 ;
        RECT 134.040 34.640 134.190 35.340 ;
        RECT 136.200 35.125 136.510 36.220 ;
        RECT 136.205 34.655 136.510 35.125 ;
        RECT 133.965 34.410 134.255 34.640 ;
        RECT 136.110 34.410 136.570 34.655 ;
        RECT 129.820 32.250 131.660 34.250 ;
        RECT 131.870 33.250 134.005 34.250 ;
        RECT 134.215 33.250 136.060 34.250 ;
        RECT 131.870 32.250 132.100 33.250 ;
        RECT 126.985 30.445 127.990 32.250 ;
        RECT 130.800 31.520 131.300 31.620 ;
        RECT 129.400 31.220 131.300 31.520 ;
        RECT 129.400 30.880 129.700 31.220 ;
        RECT 130.800 31.120 131.300 31.220 ;
        RECT 129.305 30.650 129.765 30.880 ;
        RECT 126.985 26.445 129.255 30.445 ;
        RECT 129.815 28.445 130.045 30.445 ;
        RECT 132.785 29.685 133.085 33.250 ;
        RECT 135.830 32.250 136.060 33.250 ;
        RECT 136.620 33.930 138.990 34.250 ;
        RECT 136.620 33.920 141.605 33.930 ;
        RECT 136.620 32.420 143.395 33.920 ;
        RECT 136.620 32.250 138.990 32.420 ;
        RECT 131.685 29.535 134.185 29.685 ;
        RECT 136.095 29.620 136.595 30.120 ;
        RECT 131.685 28.880 131.835 29.535 ;
        RECT 131.615 28.650 131.905 28.880 ;
        RECT 134.035 28.835 134.185 29.535 ;
        RECT 136.200 28.835 136.505 29.620 ;
        RECT 137.990 29.385 138.990 32.250 ;
        RECT 133.960 28.605 134.250 28.835 ;
        RECT 136.105 28.605 136.565 28.835 ;
        RECT 137.985 28.445 138.990 29.385 ;
        RECT 146.500 31.025 147.495 31.135 ;
        RECT 129.815 26.445 131.655 28.445 ;
        RECT 131.865 27.445 134.000 28.445 ;
        RECT 134.210 27.445 136.055 28.445 ;
        RECT 131.865 26.445 132.095 27.445 ;
        RECT 126.985 24.650 127.990 26.445 ;
        RECT 130.800 25.720 131.300 25.820 ;
        RECT 129.400 25.420 131.300 25.720 ;
        RECT 129.400 25.085 129.700 25.420 ;
        RECT 130.800 25.320 131.300 25.420 ;
        RECT 129.305 24.855 129.765 25.085 ;
        RECT 126.985 24.020 129.255 24.650 ;
        RECT 121.000 21.020 129.255 24.020 ;
        RECT 126.985 20.650 129.255 21.020 ;
        RECT 129.815 22.650 130.045 24.650 ;
        RECT 132.785 23.890 133.085 27.445 ;
        RECT 135.825 26.445 136.055 27.445 ;
        RECT 136.615 26.445 138.990 28.445 ;
        RECT 143.925 28.990 145.925 28.995 ;
        RECT 146.500 28.990 147.500 31.025 ;
        RECT 148.065 28.995 150.030 29.000 ;
        RECT 148.065 28.990 150.065 28.995 ;
        RECT 143.925 28.500 150.065 28.990 ;
        RECT 143.925 27.325 145.925 28.500 ;
        RECT 148.065 27.320 150.065 28.500 ;
        RECT 146.130 26.815 147.860 27.275 ;
        RECT 143.925 26.535 145.925 26.765 ;
        RECT 131.685 23.740 134.185 23.890 ;
        RECT 136.095 23.820 136.595 24.320 ;
        RECT 131.685 23.085 131.835 23.740 ;
        RECT 131.615 22.855 131.905 23.085 ;
        RECT 134.035 23.040 134.185 23.740 ;
        RECT 136.200 23.040 136.505 23.820 ;
        RECT 133.960 22.810 134.250 23.040 ;
        RECT 136.105 22.810 136.565 23.040 ;
        RECT 137.985 22.650 138.990 26.445 ;
        RECT 144.545 25.220 145.040 26.535 ;
        RECT 146.845 25.895 147.145 26.815 ;
        RECT 148.065 26.535 150.065 26.765 ;
        RECT 148.745 25.895 149.245 26.535 ;
        RECT 146.845 25.820 149.245 25.895 ;
        RECT 146.800 25.595 149.245 25.820 ;
        RECT 146.800 25.320 147.300 25.595 ;
        RECT 143.200 25.180 145.040 25.220 ;
        RECT 148.745 25.180 149.245 25.595 ;
        RECT 142.485 24.920 142.985 25.025 ;
        RECT 143.200 24.920 146.650 25.180 ;
        RECT 142.485 24.620 143.500 24.920 ;
        RECT 144.545 24.890 146.650 24.920 ;
        RECT 142.485 24.525 142.985 24.620 ;
        RECT 144.545 24.350 145.050 24.890 ;
        RECT 144.375 24.120 145.375 24.350 ;
        RECT 145.535 24.005 145.765 24.070 ;
        RECT 146.350 24.005 146.650 24.890 ;
        RECT 148.750 24.345 149.250 25.180 ;
        RECT 148.510 24.115 149.510 24.345 ;
        RECT 151.900 24.100 152.500 24.720 ;
        RECT 149.670 24.020 149.900 24.065 ;
        RECT 151.900 24.020 152.400 24.100 ;
        RECT 145.535 23.700 146.655 24.005 ;
        RECT 149.670 23.720 152.400 24.020 ;
        RECT 145.535 23.610 145.765 23.700 ;
        RECT 149.670 23.605 149.900 23.720 ;
        RECT 129.815 20.650 131.655 22.650 ;
        RECT 131.865 21.650 134.000 22.650 ;
        RECT 134.210 21.650 136.055 22.650 ;
        RECT 131.865 20.650 132.095 21.650 ;
        RECT 126.985 18.850 127.990 20.650 ;
        RECT 130.805 19.910 131.305 20.010 ;
        RECT 129.405 19.610 131.305 19.910 ;
        RECT 129.405 19.285 129.705 19.610 ;
        RECT 130.805 19.510 131.305 19.610 ;
        RECT 129.310 19.055 129.770 19.285 ;
        RECT 126.985 14.850 129.260 18.850 ;
        RECT 129.820 16.850 130.050 18.850 ;
        RECT 132.785 18.090 133.085 21.650 ;
        RECT 135.825 20.650 136.055 21.650 ;
        RECT 136.615 22.530 138.990 22.650 ;
        RECT 144.375 22.535 145.375 23.560 ;
        RECT 140.245 22.530 145.375 22.535 ;
        RECT 136.615 22.490 145.375 22.530 ;
        RECT 148.510 22.490 149.510 23.555 ;
        RECT 136.615 22.125 149.510 22.490 ;
        RECT 136.615 21.980 149.515 22.125 ;
        RECT 136.615 20.650 143.420 21.980 ;
        RECT 137.985 20.515 143.420 20.650 ;
        RECT 137.985 20.505 140.910 20.515 ;
        RECT 131.690 17.940 134.190 18.090 ;
        RECT 136.100 18.020 136.600 18.520 ;
        RECT 131.690 17.285 131.840 17.940 ;
        RECT 131.620 17.055 131.910 17.285 ;
        RECT 134.040 17.240 134.190 17.940 ;
        RECT 136.205 17.240 136.510 18.020 ;
        RECT 133.965 17.010 134.255 17.240 ;
        RECT 136.110 17.010 136.570 17.240 ;
        RECT 137.985 16.850 138.990 20.505 ;
        RECT 129.820 14.850 131.660 16.850 ;
        RECT 131.870 15.850 134.005 16.850 ;
        RECT 134.215 15.850 136.060 16.850 ;
        RECT 131.870 14.850 132.100 15.850 ;
        RECT 126.985 13.050 127.990 14.850 ;
        RECT 130.800 14.110 131.300 14.210 ;
        RECT 129.400 13.810 131.300 14.110 ;
        RECT 129.400 13.485 129.700 13.810 ;
        RECT 130.800 13.710 131.300 13.810 ;
        RECT 129.305 13.255 129.765 13.485 ;
        RECT 126.985 9.050 129.255 13.050 ;
        RECT 129.815 11.050 130.045 13.050 ;
        RECT 132.785 12.290 133.085 15.850 ;
        RECT 135.830 14.850 136.060 15.850 ;
        RECT 136.620 14.850 138.990 16.850 ;
        RECT 137.985 14.290 138.990 14.850 ;
        RECT 131.685 12.140 134.185 12.290 ;
        RECT 136.095 12.215 136.595 12.715 ;
        RECT 131.685 11.485 131.835 12.140 ;
        RECT 131.615 11.255 131.905 11.485 ;
        RECT 134.035 11.440 134.185 12.140 ;
        RECT 136.200 11.440 136.505 12.215 ;
        RECT 133.960 11.210 134.250 11.440 ;
        RECT 136.105 11.210 136.565 11.440 ;
        RECT 137.985 11.130 138.985 14.290 ;
        RECT 152.100 14.220 152.400 23.720 ;
        RECT 152.000 13.720 152.500 14.220 ;
        RECT 137.985 11.125 141.400 11.130 ;
        RECT 137.985 11.050 143.390 11.125 ;
        RECT 129.815 9.050 131.655 11.050 ;
        RECT 131.865 10.050 134.000 11.050 ;
        RECT 134.210 10.050 136.055 11.050 ;
        RECT 131.865 9.050 132.095 10.050 ;
        RECT 127.500 7.035 127.900 9.050 ;
        RECT 132.785 8.340 133.085 10.050 ;
        RECT 135.825 9.050 136.055 10.050 ;
        RECT 136.615 9.625 143.390 11.050 ;
        RECT 136.615 9.620 141.400 9.625 ;
        RECT 136.615 9.050 138.985 9.620 ;
        RECT 137.985 8.490 138.985 9.050 ;
        RECT 132.735 7.940 133.135 8.340 ;
        RECT 138.200 8.125 138.600 8.490 ;
        RECT 127.500 5.300 127.885 7.035 ;
        RECT 131.170 5.300 131.650 6.330 ;
        RECT 132.835 6.290 133.035 7.940 ;
        RECT 132.785 5.940 133.085 6.290 ;
        RECT 127.500 4.920 131.650 5.300 ;
        RECT 131.170 3.110 131.650 4.920 ;
        RECT 133.890 5.025 134.370 6.330 ;
        RECT 138.200 6.115 138.605 8.125 ;
        RECT 138.200 5.025 138.600 6.115 ;
        RECT 132.785 4.540 133.085 4.890 ;
        RECT 133.890 4.625 138.600 5.025 ;
        RECT 132.850 2.825 133.050 4.540 ;
        RECT 133.890 3.110 134.370 4.625 ;
        RECT 132.500 2.720 133.400 2.825 ;
        RECT 132.500 2.320 133.405 2.720 ;
      LAYER met2 ;
        RECT 82.350 223.290 84.180 224.200 ;
        RECT 44.000 221.500 44.600 221.600 ;
        RECT 80.900 221.500 81.500 221.600 ;
        RECT 86.100 221.520 86.600 221.600 ;
        RECT 44.000 221.100 81.500 221.500 ;
        RECT 85.500 221.100 86.600 221.520 ;
        RECT 44.000 220.900 44.600 221.100 ;
        RECT 80.900 221.000 81.500 221.100 ;
        RECT 82.380 218.080 84.210 218.990 ;
        RECT 140.750 217.500 142.520 218.400 ;
        RECT 114.330 206.800 116.100 207.700 ;
        RECT 114.330 199.300 116.100 200.200 ;
        RECT 114.330 191.800 116.100 192.700 ;
        RECT 114.330 184.800 116.100 185.700 ;
        RECT 114.330 177.300 116.100 178.200 ;
        RECT 114.340 169.800 116.110 170.700 ;
        RECT 114.340 162.300 116.110 163.200 ;
        RECT 44.000 123.400 44.600 138.200 ;
        RECT 77.550 135.240 79.040 135.250 ;
        RECT 76.560 132.750 79.040 135.240 ;
        RECT 103.600 135.010 104.400 136.600 ;
        RECT 77.710 132.740 79.040 132.750 ;
        RECT 102.370 130.940 103.170 132.540 ;
        RECT 114.400 131.000 116.000 131.800 ;
        RECT 101.600 130.300 103.190 130.570 ;
        RECT 111.880 130.300 112.310 130.360 ;
        RECT 101.600 130.050 112.310 130.300 ;
        RECT 101.600 129.770 103.190 130.050 ;
        RECT 111.880 129.970 112.310 130.050 ;
        RECT 109.700 127.520 112.210 128.520 ;
        RECT 109.700 127.020 112.220 127.520 ;
        RECT 109.710 126.020 112.220 127.020 ;
        RECT 43.010 122.600 43.510 122.700 ;
        RECT 43.010 122.300 45.510 122.600 ;
        RECT 43.010 122.200 43.510 122.300 ;
        RECT 44.100 115.100 44.460 115.130 ;
        RECT 45.210 115.100 45.510 122.300 ;
        RECT 44.100 114.800 45.510 115.100 ;
        RECT 44.100 114.770 44.460 114.800 ;
        RECT 43.010 112.090 43.510 112.190 ;
        RECT 43.010 111.790 45.510 112.090 ;
        RECT 43.010 111.690 43.510 111.790 ;
        RECT 44.100 104.590 44.460 104.620 ;
        RECT 45.210 104.590 45.510 111.790 ;
        RECT 44.100 104.290 45.510 104.590 ;
        RECT 44.100 104.260 44.460 104.290 ;
        RECT 43.010 101.600 43.510 101.700 ;
        RECT 43.010 101.300 45.510 101.600 ;
        RECT 43.010 101.200 43.510 101.300 ;
        RECT 44.100 94.100 44.460 94.130 ;
        RECT 45.210 94.100 45.510 101.300 ;
        RECT 44.100 93.800 45.510 94.100 ;
        RECT 44.100 93.770 44.460 93.800 ;
        RECT 43.010 91.090 43.510 91.190 ;
        RECT 43.010 90.790 45.510 91.090 ;
        RECT 43.010 90.690 43.510 90.790 ;
        RECT 33.500 80.500 38.500 84.000 ;
        RECT 44.100 83.590 44.460 83.620 ;
        RECT 45.210 83.590 45.510 90.790 ;
        RECT 48.580 84.500 53.580 88.000 ;
        RECT 44.100 83.290 45.510 83.590 ;
        RECT 44.100 83.260 44.460 83.290 ;
        RECT 43.010 80.600 43.510 80.700 ;
        RECT 43.010 80.300 45.510 80.600 ;
        RECT 43.010 80.200 43.510 80.300 ;
        RECT 44.100 73.100 44.460 73.130 ;
        RECT 45.210 73.100 45.510 80.300 ;
        RECT 44.100 72.800 45.510 73.100 ;
        RECT 44.100 72.770 44.460 72.800 ;
        RECT 43.010 70.090 43.510 70.190 ;
        RECT 43.010 69.790 45.510 70.090 ;
        RECT 43.010 69.690 43.510 69.790 ;
        RECT 44.100 62.590 44.460 62.620 ;
        RECT 45.210 62.590 45.510 69.790 ;
        RECT 44.100 62.290 45.510 62.590 ;
        RECT 44.100 62.260 44.460 62.290 ;
        RECT 43.400 55.800 44.000 56.400 ;
        RECT 43.500 2.310 43.900 55.800 ;
        RECT 151.000 54.480 153.510 56.990 ;
        RECT 120.995 45.020 147.485 46.020 ;
        RECT 120.995 33.025 121.995 45.020 ;
        RECT 130.795 37.620 131.305 37.720 ;
        RECT 136.100 37.620 136.600 37.720 ;
        RECT 130.795 37.320 136.600 37.620 ;
        RECT 130.795 37.220 131.305 37.320 ;
        RECT 136.100 37.220 136.600 37.320 ;
        RECT 136.100 36.915 136.600 37.020 ;
        RECT 139.300 36.915 139.600 36.920 ;
        RECT 136.100 36.615 139.600 36.915 ;
        RECT 136.100 36.520 136.600 36.615 ;
        RECT 132.685 36.190 133.185 36.290 ;
        RECT 132.685 35.890 137.985 36.190 ;
        RECT 132.685 35.790 133.185 35.890 ;
        RECT 120.990 24.020 122.000 33.025 ;
        RECT 130.800 31.520 131.300 31.620 ;
        RECT 136.100 31.520 136.600 31.620 ;
        RECT 130.800 31.220 136.600 31.520 ;
        RECT 130.800 31.120 131.300 31.220 ;
        RECT 136.100 31.125 136.600 31.220 ;
        RECT 136.095 30.320 136.600 30.820 ;
        RECT 136.195 30.120 136.500 30.320 ;
        RECT 136.095 29.620 136.595 30.120 ;
        RECT 130.800 25.720 131.300 25.820 ;
        RECT 136.100 25.720 136.600 25.820 ;
        RECT 130.800 25.420 136.600 25.720 ;
        RECT 130.800 25.320 131.300 25.420 ;
        RECT 136.100 25.320 136.600 25.420 ;
        RECT 136.095 24.520 136.600 25.020 ;
        RECT 136.195 24.320 136.500 24.520 ;
        RECT 115.000 21.020 126.985 24.020 ;
        RECT 136.095 23.820 136.595 24.320 ;
        RECT 130.805 19.920 131.305 20.010 ;
        RECT 136.100 19.920 136.605 20.020 ;
        RECT 130.805 19.620 136.605 19.920 ;
        RECT 130.805 19.510 131.305 19.620 ;
        RECT 136.100 19.520 136.605 19.620 ;
        RECT 136.100 18.720 136.605 19.220 ;
        RECT 136.200 18.520 136.505 18.720 ;
        RECT 136.100 18.020 136.600 18.520 ;
        RECT 130.800 14.120 131.300 14.210 ;
        RECT 136.100 14.120 136.600 14.220 ;
        RECT 130.800 13.815 136.600 14.120 ;
        RECT 130.800 13.710 131.300 13.815 ;
        RECT 136.100 13.720 136.600 13.815 ;
        RECT 136.095 12.915 136.600 13.415 ;
        RECT 136.195 12.715 136.500 12.915 ;
        RECT 136.095 12.215 136.595 12.715 ;
        RECT 132.735 8.290 133.135 8.340 ;
        RECT 137.685 8.290 137.985 35.890 ;
        RECT 139.300 30.820 139.600 36.615 ;
        RECT 140.700 32.420 146.000 33.920 ;
        RECT 146.505 32.525 147.485 45.020 ;
        RECT 146.500 31.520 147.495 32.525 ;
        RECT 146.500 31.020 147.500 31.520 ;
        RECT 139.200 30.320 139.700 30.820 ;
        RECT 139.300 25.015 139.600 30.320 ;
        RECT 146.500 28.990 147.495 31.020 ;
        RECT 142.495 25.720 143.005 25.825 ;
        RECT 146.800 25.720 147.300 25.820 ;
        RECT 142.495 25.425 147.300 25.720 ;
        RECT 142.495 25.320 143.005 25.425 ;
        RECT 146.800 25.320 147.300 25.425 ;
        RECT 139.200 24.925 139.700 25.015 ;
        RECT 142.485 24.925 142.985 25.025 ;
        RECT 139.200 24.615 142.985 24.925 ;
        RECT 152.000 24.720 152.400 54.480 ;
        RECT 139.200 24.515 139.700 24.615 ;
        RECT 142.485 24.525 142.985 24.615 ;
        RECT 139.300 19.220 139.600 24.515 ;
        RECT 151.900 24.100 152.500 24.720 ;
        RECT 139.200 18.720 139.700 19.220 ;
        RECT 139.300 13.420 139.600 18.720 ;
        RECT 139.200 12.920 139.700 13.420 ;
        RECT 140.700 10.470 143.420 22.530 ;
        RECT 152.000 13.720 152.500 14.220 ;
        RECT 152.100 13.320 152.400 13.720 ;
        RECT 152.000 12.820 152.500 13.320 ;
        RECT 140.700 9.625 143.390 10.470 ;
        RECT 132.735 7.990 137.985 8.290 ;
        RECT 132.735 7.935 133.135 7.990 ;
        RECT 132.500 2.720 133.400 2.825 ;
        RECT 132.500 2.320 133.405 2.720 ;
        RECT 43.400 1.700 44.000 2.310 ;
        RECT 132.500 1.820 133.400 2.320 ;
      LAYER met3 ;
        RECT 32.550 222.550 67.950 223.470 ;
        RECT 81.320 223.280 83.310 224.200 ;
        RECT 32.550 218.470 33.470 222.550 ;
        RECT 0.980 217.550 33.470 218.470 ;
        RECT 44.000 137.600 44.600 221.600 ;
        RECT 67.030 219.000 67.950 222.550 ;
        RECT 86.100 221.100 87.100 221.600 ;
        RECT 67.030 218.080 83.340 219.000 ;
        RECT 139.860 217.500 141.650 218.400 ;
        RECT 115.200 207.500 116.100 207.700 ;
        RECT 135.300 207.500 136.210 207.700 ;
        RECT 115.200 207.000 136.210 207.500 ;
        RECT 115.200 206.800 116.100 207.000 ;
        RECT 135.300 206.800 136.210 207.000 ;
        RECT 115.200 200.000 116.100 200.200 ;
        RECT 132.490 200.000 133.400 200.200 ;
        RECT 115.200 199.500 133.400 200.000 ;
        RECT 115.200 199.300 116.100 199.500 ;
        RECT 132.490 199.300 133.400 199.500 ;
        RECT 115.200 192.500 116.100 192.700 ;
        RECT 129.700 192.500 130.610 192.700 ;
        RECT 115.200 192.000 130.610 192.500 ;
        RECT 115.200 191.800 116.100 192.000 ;
        RECT 129.700 191.800 130.610 192.000 ;
        RECT 115.200 185.500 116.100 185.700 ;
        RECT 126.980 185.500 127.890 185.700 ;
        RECT 115.200 185.000 127.890 185.500 ;
        RECT 115.200 184.800 116.100 185.000 ;
        RECT 126.980 184.800 127.890 185.000 ;
        RECT 115.200 178.000 116.100 178.200 ;
        RECT 124.200 178.000 125.110 178.200 ;
        RECT 115.200 177.500 125.110 178.000 ;
        RECT 115.200 177.300 116.100 177.500 ;
        RECT 124.200 177.300 125.110 177.500 ;
        RECT 115.210 170.510 116.110 170.700 ;
        RECT 121.440 170.510 122.350 170.710 ;
        RECT 115.210 170.010 122.350 170.510 ;
        RECT 115.210 169.800 116.110 170.010 ;
        RECT 121.440 169.810 122.350 170.010 ;
        RECT 115.210 163.000 116.110 163.200 ;
        RECT 118.640 163.000 119.550 163.200 ;
        RECT 115.210 162.500 119.550 163.000 ;
        RECT 115.210 162.300 116.110 162.500 ;
        RECT 118.640 162.300 119.550 162.500 ;
        RECT 1.000 135.820 104.400 136.610 ;
        RECT 103.600 135.810 104.400 135.820 ;
        RECT 76.560 135.240 77.530 135.270 ;
        RECT 3.980 132.750 78.050 135.240 ;
        RECT 3.980 132.740 6.210 132.750 ;
        RECT 75.260 130.580 76.080 132.750 ;
        RECT 77.710 132.740 78.050 132.750 ;
        RECT 102.370 131.740 103.170 133.340 ;
        RECT 115.200 131.000 116.800 131.800 ;
        RECT 75.260 130.570 102.370 130.580 ;
        RECT 75.260 129.770 102.390 130.570 ;
        RECT 75.260 129.760 102.370 129.770 ;
        RECT 109.710 127.000 112.220 127.520 ;
        RECT 109.680 126.520 112.240 127.000 ;
        RECT 109.680 125.070 112.255 126.520 ;
        RECT 51.080 84.500 59.560 88.000 ;
        RECT 1.000 80.500 36.000 84.000 ;
        RECT 56.060 51.025 59.560 84.500 ;
        RECT 109.680 57.065 112.250 125.070 ;
        RECT 109.680 56.990 153.495 57.065 ;
        RECT 109.680 54.495 153.510 56.990 ;
        RECT 151.000 54.480 153.510 54.495 ;
        RECT 4.000 51.020 6.000 51.025 ;
        RECT 30.010 51.020 158.010 51.025 ;
        RECT 4.000 48.020 158.010 51.020 ;
        RECT 5.000 48.015 35.010 48.020 ;
        RECT 155.500 47.800 158.010 48.020 ;
        RECT 136.100 37.620 136.600 37.720 ;
        RECT 136.100 37.320 140.300 37.620 ;
        RECT 136.100 37.220 136.600 37.320 ;
        RECT 136.100 31.520 136.600 31.620 ;
        RECT 140.000 31.520 140.300 37.320 ;
        RECT 155.500 33.920 158.030 47.800 ;
        RECT 143.400 32.420 158.030 33.920 ;
        RECT 136.100 31.220 140.300 31.520 ;
        RECT 136.100 31.125 136.600 31.220 ;
        RECT 136.095 30.720 136.600 30.820 ;
        RECT 139.200 30.720 139.700 30.820 ;
        RECT 136.095 30.420 139.700 30.720 ;
        RECT 136.095 30.320 136.600 30.420 ;
        RECT 139.200 30.320 139.700 30.420 ;
        RECT 136.100 25.720 136.600 25.820 ;
        RECT 140.000 25.720 140.300 31.220 ;
        RECT 142.495 25.720 143.005 25.825 ;
        RECT 136.100 25.420 143.005 25.720 ;
        RECT 136.100 25.320 136.600 25.420 ;
        RECT 136.095 24.920 136.600 25.020 ;
        RECT 139.200 24.920 139.700 25.015 ;
        RECT 136.095 24.620 139.700 24.920 ;
        RECT 136.095 24.520 136.600 24.620 ;
        RECT 139.200 24.515 139.700 24.620 ;
        RECT 1.000 24.010 32.005 24.020 ;
        RECT 112.000 24.010 121.000 24.020 ;
        RECT 1.000 21.030 121.000 24.010 ;
        RECT 1.000 21.015 32.005 21.030 ;
        RECT 112.000 21.020 121.000 21.030 ;
        RECT 112.000 20.990 115.000 21.020 ;
        RECT 136.100 19.920 136.605 20.020 ;
        RECT 140.000 19.920 140.300 25.420 ;
        RECT 142.495 25.320 143.005 25.420 ;
        RECT 136.100 19.620 140.300 19.920 ;
        RECT 136.100 19.520 136.605 19.620 ;
        RECT 136.100 19.120 136.605 19.220 ;
        RECT 139.200 19.120 139.700 19.220 ;
        RECT 136.100 18.820 139.700 19.120 ;
        RECT 136.100 18.720 136.605 18.820 ;
        RECT 139.200 18.720 139.700 18.820 ;
        RECT 136.100 14.120 136.600 14.220 ;
        RECT 140.000 14.120 140.300 19.620 ;
        RECT 155.500 20.150 158.030 32.420 ;
        RECT 140.710 18.015 148.010 18.030 ;
        RECT 155.500 18.015 158.000 20.150 ;
        RECT 140.710 15.530 158.000 18.015 ;
        RECT 140.990 15.515 158.000 15.530 ;
        RECT 140.990 15.500 148.010 15.515 ;
        RECT 136.100 13.820 140.300 14.120 ;
        RECT 136.100 13.720 136.600 13.820 ;
        RECT 136.095 13.320 136.600 13.415 ;
        RECT 139.200 13.320 139.700 13.420 ;
        RECT 136.095 13.020 139.700 13.320 ;
        RECT 136.095 12.915 136.600 13.020 ;
        RECT 139.200 12.920 139.700 13.020 ;
        RECT 152.000 12.820 152.500 13.320 ;
        RECT 43.400 2.280 44.000 2.310 ;
        RECT 132.500 2.300 133.400 2.320 ;
        RECT 132.100 2.280 133.400 2.300 ;
        RECT 43.400 1.800 133.400 2.280 ;
        RECT 152.100 2.220 152.400 12.820 ;
        RECT 43.400 1.700 44.000 1.800 ;
        RECT 132.490 1.000 133.400 1.800 ;
        RECT 151.800 1.020 152.700 2.220 ;
      LAYER met4 ;
        RECT 30.970 224.760 33.430 225.060 ;
        RECT 33.730 224.760 36.190 225.060 ;
        RECT 36.490 224.760 38.950 225.060 ;
        RECT 39.250 224.760 41.710 225.060 ;
        RECT 42.010 224.760 44.470 225.060 ;
        RECT 44.770 224.760 47.230 225.060 ;
        RECT 47.530 224.760 49.990 225.060 ;
        RECT 50.290 224.760 52.750 225.060 ;
        RECT 53.050 224.760 55.510 225.060 ;
        RECT 55.810 224.760 58.270 225.060 ;
        RECT 58.570 224.760 61.030 225.060 ;
        RECT 61.330 224.760 63.790 225.060 ;
        RECT 64.090 224.760 66.550 225.060 ;
        RECT 66.850 224.760 69.310 225.060 ;
        RECT 69.610 224.760 72.070 225.060 ;
        RECT 72.370 224.760 74.830 225.060 ;
        RECT 75.130 224.760 77.590 225.060 ;
        RECT 77.890 224.760 80.350 225.060 ;
        RECT 80.650 224.760 83.110 225.060 ;
        RECT 83.410 224.760 85.870 225.060 ;
        RECT 86.170 224.760 88.630 225.060 ;
        RECT 88.930 224.760 91.390 225.060 ;
        RECT 30.680 224.325 82.200 224.760 ;
        RECT 30.680 220.170 31.475 224.325 ;
        RECT 81.320 223.270 82.200 224.325 ;
        RECT 86.600 221.500 87.100 221.600 ;
        RECT 94.150 221.500 94.450 224.760 ;
        RECT 86.600 221.200 94.450 221.500 ;
        RECT 86.600 221.100 87.100 221.200 ;
        RECT 6.000 219.500 31.505 220.170 ;
        RECT 102.560 134.530 105.790 134.830 ;
        RECT 102.560 133.340 102.860 134.530 ;
        RECT 105.490 133.480 105.790 134.530 ;
        RECT 116.230 133.480 116.530 224.760 ;
        RECT 118.990 163.200 119.290 224.760 ;
        RECT 121.750 170.710 122.050 224.760 ;
        RECT 124.510 178.200 124.810 224.760 ;
        RECT 127.270 185.700 127.570 224.760 ;
        RECT 130.030 192.700 130.330 224.760 ;
        RECT 132.790 200.200 133.090 224.760 ;
        RECT 135.550 207.700 135.850 224.760 ;
        RECT 138.310 218.060 138.610 224.760 ;
        RECT 139.860 218.060 140.760 218.400 ;
        RECT 138.310 217.760 140.760 218.060 ;
        RECT 139.860 217.500 140.760 217.760 ;
        RECT 135.300 206.800 136.210 207.700 ;
        RECT 132.490 199.300 133.400 200.200 ;
        RECT 129.700 191.800 130.610 192.700 ;
        RECT 126.980 184.800 127.890 185.700 ;
        RECT 124.200 177.300 125.110 178.200 ;
        RECT 121.440 169.810 122.350 170.710 ;
        RECT 118.640 162.300 119.550 163.200 ;
        RECT 102.370 132.540 103.170 133.340 ;
        RECT 105.490 133.180 116.530 133.480 ;
        RECT 116.230 131.800 116.530 133.180 ;
        RECT 116.000 131.000 116.800 131.800 ;
        RECT 132.490 1.000 133.400 1.820 ;
        RECT 151.810 1.000 152.720 1.820 ;
  END
END tt_um_Madd_CS_Ring_Osc
END LIBRARY

